VERSION 5.7 ;
  NOWIREEXTENSIONATPIN ON ;
  DIVIDERCHAR "/" ;
  BUSBITCHARS "[]" ;
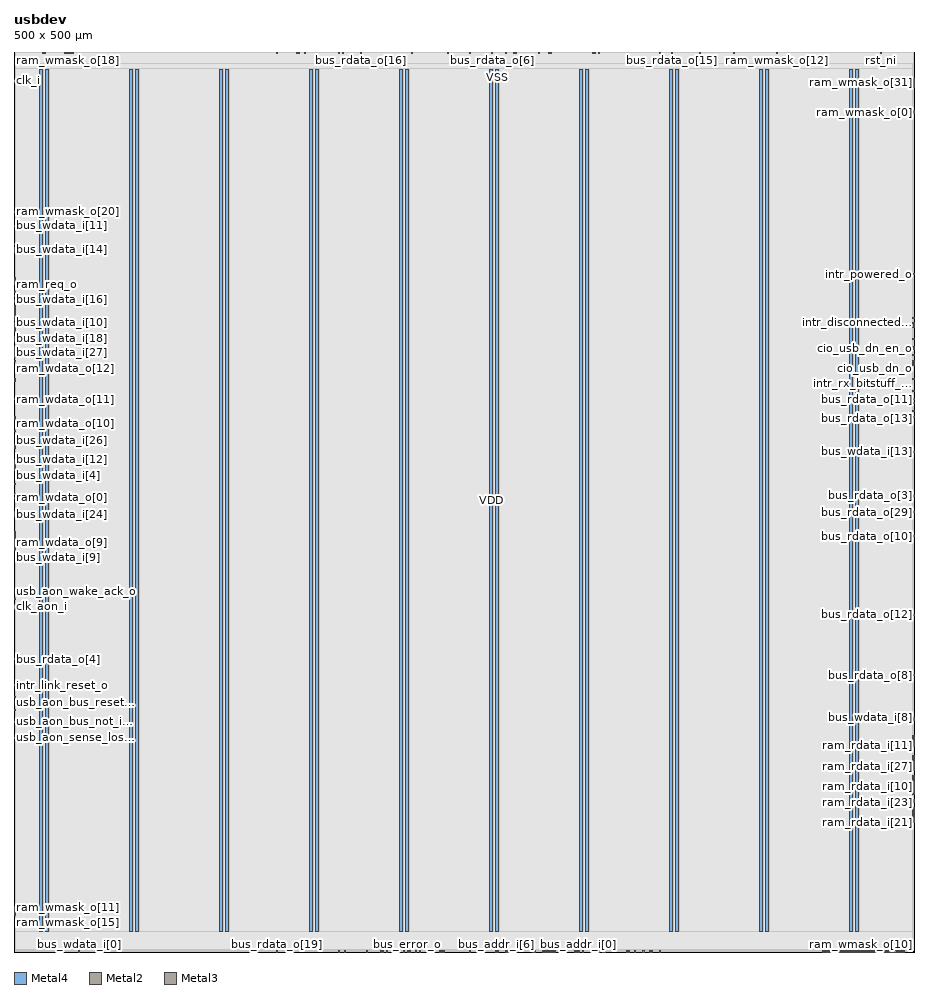
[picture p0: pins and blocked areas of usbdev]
MACRO usbdev
  CLASS BLOCK ;
  FOREIGN usbdev ;
  ORIGIN 0.000 0.000 ;
  SIZE 500.000 BY 500.000 ;
  PIN VDD
    DIRECTION INOUT ;
    USE POWER ;
    PORT
      LAYER Metal4 ;
        RECT 14.280 11.460 15.880 490.300 ;
    END
    PORT
      LAYER Metal4 ;
        RECT 64.280 11.460 65.880 490.300 ;
    END
    PORT
      LAYER Metal4 ;
        RECT 114.280 11.460 115.880 490.300 ;
    END
    PORT
      LAYER Metal4 ;
        RECT 164.280 11.460 165.880 490.300 ;
    END
    PORT
      LAYER Metal4 ;
        RECT 214.280 11.460 215.880 490.300 ;
    END
    PORT
      LAYER Metal4 ;
        RECT 264.280 11.460 265.880 490.300 ;
    END
    PORT
      LAYER Metal4 ;
        RECT 314.280 11.460 315.880 490.300 ;
    END
    PORT
      LAYER Metal4 ;
        RECT 364.280 11.460 365.880 490.300 ;
    END
    PORT
      LAYER Metal4 ;
        RECT 414.280 11.460 415.880 490.300 ;
    END
    PORT
      LAYER Metal4 ;
        RECT 464.280 11.460 465.880 490.300 ;
    END
  END VDD
  PIN VSS
    DIRECTION INOUT ;
    USE GROUND ;
    PORT
      LAYER Metal4 ;
        RECT 17.580 11.460 19.180 490.300 ;
    END
    PORT
      LAYER Metal4 ;
        RECT 67.580 11.460 69.180 490.300 ;
    END
    PORT
      LAYER Metal4 ;
        RECT 117.580 11.460 119.180 490.300 ;
    END
    PORT
      LAYER Metal4 ;
        RECT 167.580 11.460 169.180 490.300 ;
    END
    PORT
      LAYER Metal4 ;
        RECT 217.580 11.460 219.180 490.300 ;
    END
    PORT
      LAYER Metal4 ;
        RECT 267.580 11.460 269.180 490.300 ;
    END
    PORT
      LAYER Metal4 ;
        RECT 317.580 11.460 319.180 490.300 ;
    END
    PORT
      LAYER Metal4 ;
        RECT 367.580 11.460 369.180 490.300 ;
    END
    PORT
      LAYER Metal4 ;
        RECT 417.580 11.460 419.180 490.300 ;
    END
    PORT
      LAYER Metal4 ;
        RECT 467.580 11.460 469.180 490.300 ;
    END
  END VSS
  PIN bus_addr_i[0]
    DIRECTION INPUT ;
    USE SIGNAL ;
    ANTENNAGATEAREA 3.332000 ;
    ANTENNADIFFAREA 1.315500 ;
    PORT
      LAYER Metal2 ;
        RECT 313.600 0.000 314.160 0.560 ;
    END
  END bus_addr_i[0]
  PIN bus_addr_i[10]
    DIRECTION INPUT ;
    USE SIGNAL ;
    ANTENNAGATEAREA 3.998400 ;
    ANTENNADIFFAREA 1.754000 ;
    PORT
      LAYER Metal2 ;
        RECT 295.680 0.000 296.240 0.560 ;
    END
  END bus_addr_i[10]
  PIN bus_addr_i[11]
    DIRECTION INPUT ;
    USE SIGNAL ;
    ANTENNAGATEAREA 3.332000 ;
    ANTENNADIFFAREA 1.315500 ;
    PORT
      LAYER Metal2 ;
        RECT 296.800 0.000 297.360 0.560 ;
    END
  END bus_addr_i[11]
  PIN bus_addr_i[1]
    DIRECTION INPUT ;
    USE SIGNAL ;
    ANTENNAGATEAREA 3.332000 ;
    ANTENNADIFFAREA 1.315500 ;
    PORT
      LAYER Metal2 ;
        RECT 311.360 0.000 311.920 0.560 ;
    END
  END bus_addr_i[1]
  PIN bus_addr_i[2]
    DIRECTION INPUT ;
    USE SIGNAL ;
    ANTENNAGATEAREA 10.662399 ;
    ANTENNADIFFAREA 4.385000 ;
    PORT
      LAYER Metal2 ;
        RECT 287.840 0.000 288.400 0.560 ;
    END
  END bus_addr_i[2]
  PIN bus_addr_i[3]
    DIRECTION INPUT ;
    USE SIGNAL ;
    ANTENNAGATEAREA 6.664000 ;
    ANTENNADIFFAREA 2.631000 ;
    PORT
      LAYER Metal2 ;
        RECT 288.960 0.000 289.520 0.560 ;
    END
  END bus_addr_i[3]
  PIN bus_addr_i[4]
    DIRECTION INPUT ;
    USE SIGNAL ;
    ANTENNAGATEAREA 4.664800 ;
    ANTENNADIFFAREA 2.192500 ;
    PORT
      LAYER Metal2 ;
        RECT 294.560 0.000 295.120 0.560 ;
    END
  END bus_addr_i[4]
  PIN bus_addr_i[5]
    DIRECTION INPUT ;
    USE SIGNAL ;
    ANTENNAGATEAREA 5.997600 ;
    ANTENNADIFFAREA 2.631000 ;
    PORT
      LAYER Metal2 ;
        RECT 293.440 0.000 294.000 0.560 ;
    END
  END bus_addr_i[5]
  PIN bus_addr_i[6]
    DIRECTION INPUT ;
    USE SIGNAL ;
    ANTENNAGATEAREA 3.998400 ;
    ANTENNADIFFAREA 1.754000 ;
    PORT
      LAYER Metal2 ;
        RECT 267.680 0.000 268.240 0.560 ;
    END
  END bus_addr_i[6]
  PIN bus_addr_i[7]
    DIRECTION INPUT ;
    USE SIGNAL ;
    ANTENNAGATEAREA 3.998400 ;
    ANTENNADIFFAREA 1.754000 ;
    PORT
      LAYER Metal2 ;
        RECT 268.800 0.000 269.360 0.560 ;
    END
  END bus_addr_i[7]
  PIN bus_addr_i[8]
    DIRECTION INPUT ;
    USE SIGNAL ;
    ANTENNAGATEAREA 3.998400 ;
    ANTENNADIFFAREA 1.754000 ;
    PORT
      LAYER Metal2 ;
        RECT 297.920 0.000 298.480 0.560 ;
    END
  END bus_addr_i[8]
  PIN bus_addr_i[9]
    DIRECTION INPUT ;
    USE SIGNAL ;
    ANTENNAGATEAREA 3.998400 ;
    ANTENNADIFFAREA 1.754000 ;
    PORT
      LAYER Metal2 ;
        RECT 300.160 0.000 300.720 0.560 ;
    END
  END bus_addr_i[9]
  PIN bus_be_i[0]
    DIRECTION INPUT ;
    USE SIGNAL ;
    ANTENNAGATEAREA 1.332800 ;
    ANTENNADIFFAREA 0.877000 ;
    PORT
      LAYER Metal2 ;
        RECT 238.560 0.000 239.120 0.560 ;
    END
  END bus_be_i[0]
  PIN bus_be_i[1]
    DIRECTION INPUT ;
    USE SIGNAL ;
    ANTENNAGATEAREA 0.666400 ;
    ANTENNADIFFAREA 0.438500 ;
    PORT
      LAYER Metal2 ;
        RECT 236.320 0.000 236.880 0.560 ;
    END
  END bus_be_i[1]
  PIN bus_be_i[2]
    DIRECTION INPUT ;
    USE SIGNAL ;
    ANTENNAGATEAREA 1.332800 ;
    ANTENNADIFFAREA 0.438500 ;
    PORT
      LAYER Metal2 ;
        RECT 237.440 0.000 238.000 0.560 ;
    END
  END bus_be_i[2]
  PIN bus_be_i[3]
    DIRECTION INPUT ;
    USE SIGNAL ;
    ANTENNAGATEAREA 1.332800 ;
    ANTENNADIFFAREA 0.438500 ;
    PORT
      LAYER Metal2 ;
        RECT 230.720 0.000 231.280 0.560 ;
    END
  END bus_be_i[3]
  PIN bus_error_o
    DIRECTION OUTPUT ;
    USE SIGNAL ;
    ANTENNAGATEAREA 0.666400 ;
    ANTENNADIFFAREA 1.237600 ;
    PORT
      LAYER Metal2 ;
        RECT 218.400 0.000 218.960 0.560 ;
    END
  END bus_error_o
  PIN bus_rdata_o[0]
    DIRECTION OUTPUT ;
    USE SIGNAL ;
    ANTENNADIFFAREA 1.237600 ;
    PORT
      LAYER Metal2 ;
        RECT 253.120 0.000 253.680 0.560 ;
    END
  END bus_rdata_o[0]
  PIN bus_rdata_o[10]
    DIRECTION OUTPUT ;
    USE SIGNAL ;
    ANTENNADIFFAREA 1.955200 ;
    PORT
      LAYER Metal3 ;
        RECT 499.440 230.720 500.000 231.280 ;
    END
  END bus_rdata_o[10]
  PIN bus_rdata_o[11]
    DIRECTION OUTPUT ;
    USE SIGNAL ;
    ANTENNADIFFAREA 1.955200 ;
    PORT
      LAYER Metal3 ;
        RECT 499.440 306.880 500.000 307.440 ;
    END
  END bus_rdata_o[11]
  PIN bus_rdata_o[12]
    DIRECTION OUTPUT ;
    USE SIGNAL ;
    ANTENNADIFFAREA 3.390400 ;
    PORT
      LAYER Metal3 ;
        RECT 499.440 187.040 500.000 187.600 ;
    END
  END bus_rdata_o[12]
  PIN bus_rdata_o[13]
    DIRECTION OUTPUT ;
    USE SIGNAL ;
    ANTENNADIFFAREA 1.955200 ;
    PORT
      LAYER Metal3 ;
        RECT 499.440 300.160 500.000 300.720 ;
    END
  END bus_rdata_o[13]
  PIN bus_rdata_o[14]
    DIRECTION OUTPUT ;
    USE SIGNAL ;
    ANTENNADIFFAREA 1.955200 ;
    PORT
      LAYER Metal3 ;
        RECT 499.440 296.800 500.000 297.360 ;
    END
  END bus_rdata_o[14]
  PIN bus_rdata_o[15]
    DIRECTION OUTPUT ;
    USE SIGNAL ;
    ANTENNADIFFAREA 1.237600 ;
    PORT
      LAYER Metal2 ;
        RECT 365.120 499.440 365.680 500.000 ;
    END
  END bus_rdata_o[15]
  PIN bus_rdata_o[16]
    DIRECTION OUTPUT ;
    USE SIGNAL ;
    ANTENNADIFFAREA 1.237600 ;
    PORT
      LAYER Metal2 ;
        RECT 192.640 499.440 193.200 500.000 ;
    END
  END bus_rdata_o[16]
  PIN bus_rdata_o[17]
    DIRECTION OUTPUT ;
    USE SIGNAL ;
    ANTENNADIFFAREA 1.237600 ;
    PORT
      LAYER Metal2 ;
        RECT 156.800 499.440 157.360 500.000 ;
    END
  END bus_rdata_o[17]
  PIN bus_rdata_o[18]
    DIRECTION OUTPUT ;
    USE SIGNAL ;
    ANTENNADIFFAREA 1.237600 ;
    PORT
      LAYER Metal2 ;
        RECT 145.600 499.440 146.160 500.000 ;
    END
  END bus_rdata_o[18]
  PIN bus_rdata_o[19]
    DIRECTION OUTPUT ;
    USE SIGNAL ;
    ANTENNADIFFAREA 1.237600 ;
    PORT
      LAYER Metal2 ;
        RECT 145.600 0.000 146.160 0.560 ;
    END
  END bus_rdata_o[19]
  PIN bus_rdata_o[1]
    DIRECTION OUTPUT ;
    USE SIGNAL ;
    ANTENNADIFFAREA 2.672800 ;
    PORT
      LAYER Metal2 ;
        RECT 260.960 0.000 261.520 0.560 ;
    END
  END bus_rdata_o[1]
  PIN bus_rdata_o[20]
    DIRECTION OUTPUT ;
    USE SIGNAL ;
    ANTENNADIFFAREA 1.237600 ;
    PORT
      LAYER Metal2 ;
        RECT 161.280 499.440 161.840 500.000 ;
    END
  END bus_rdata_o[20]
  PIN bus_rdata_o[21]
    DIRECTION OUTPUT ;
    USE SIGNAL ;
    ANTENNADIFFAREA 1.237600 ;
    PORT
      LAYER Metal2 ;
        RECT 180.320 499.440 180.880 500.000 ;
    END
  END bus_rdata_o[21]
  PIN bus_rdata_o[22]
    DIRECTION OUTPUT ;
    USE SIGNAL ;
    ANTENNADIFFAREA 1.237600 ;
    PORT
      LAYER Metal2 ;
        RECT 183.680 0.000 184.240 0.560 ;
    END
  END bus_rdata_o[22]
  PIN bus_rdata_o[23]
    DIRECTION OUTPUT ;
    USE SIGNAL ;
    ANTENNADIFFAREA 1.237600 ;
    PORT
      LAYER Metal2 ;
        RECT 353.920 0.000 354.480 0.560 ;
    END
  END bus_rdata_o[23]
  PIN bus_rdata_o[24]
    DIRECTION OUTPUT ;
    USE SIGNAL ;
    ANTENNADIFFAREA 1.439900 ;
    PORT
      LAYER Metal2 ;
        RECT 196.000 0.000 196.560 0.560 ;
    END
  END bus_rdata_o[24]
  PIN bus_rdata_o[25]
    DIRECTION OUTPUT ;
    USE SIGNAL ;
    ANTENNADIFFAREA 1.439900 ;
    PORT
      LAYER Metal2 ;
        RECT 203.840 0.000 204.400 0.560 ;
    END
  END bus_rdata_o[25]
  PIN bus_rdata_o[26]
    DIRECTION OUTPUT ;
    USE SIGNAL ;
    ANTENNADIFFAREA 1.439900 ;
    PORT
      LAYER Metal2 ;
        RECT 207.200 0.000 207.760 0.560 ;
    END
  END bus_rdata_o[26]
  PIN bus_rdata_o[27]
    DIRECTION OUTPUT ;
    USE SIGNAL ;
    ANTENNADIFFAREA 1.237600 ;
    PORT
      LAYER Metal2 ;
        RECT 219.520 0.000 220.080 0.560 ;
    END
  END bus_rdata_o[27]
  PIN bus_rdata_o[28]
    DIRECTION OUTPUT ;
    USE SIGNAL ;
    ANTENNADIFFAREA 1.439900 ;
    PORT
      LAYER Metal2 ;
        RECT 220.640 499.440 221.200 500.000 ;
    END
  END bus_rdata_o[28]
  PIN bus_rdata_o[29]
    DIRECTION OUTPUT ;
    USE SIGNAL ;
    ANTENNADIFFAREA 1.237600 ;
    PORT
      LAYER Metal3 ;
        RECT 499.440 244.160 500.000 244.720 ;
    END
  END bus_rdata_o[29]
  PIN bus_rdata_o[2]
    DIRECTION OUTPUT ;
    USE SIGNAL ;
    ANTENNADIFFAREA 1.955200 ;
    PORT
      LAYER Metal3 ;
        RECT 499.440 304.640 500.000 305.200 ;
    END
  END bus_rdata_o[2]
  PIN bus_rdata_o[30]
    DIRECTION OUTPUT ;
    USE SIGNAL ;
    ANTENNADIFFAREA 1.237600 ;
    PORT
      LAYER Metal2 ;
        RECT 349.440 0.000 350.000 0.560 ;
    END
  END bus_rdata_o[30]
  PIN bus_rdata_o[31]
    DIRECTION OUTPUT ;
    USE SIGNAL ;
    ANTENNADIFFAREA 1.237600 ;
    PORT
      LAYER Metal2 ;
        RECT 321.440 0.000 322.000 0.560 ;
    END
  END bus_rdata_o[31]
  PIN bus_rdata_o[3]
    DIRECTION OUTPUT ;
    USE SIGNAL ;
    ANTENNADIFFAREA 1.955200 ;
    PORT
      LAYER Metal3 ;
        RECT 499.440 253.120 500.000 253.680 ;
    END
  END bus_rdata_o[3]
  PIN bus_rdata_o[4]
    DIRECTION OUTPUT ;
    USE SIGNAL ;
    ANTENNADIFFAREA 1.955200 ;
    PORT
      LAYER Metal3 ;
        RECT 0.000 162.400 0.560 162.960 ;
    END
  END bus_rdata_o[4]
  PIN bus_rdata_o[5]
    DIRECTION OUTPUT ;
    USE SIGNAL ;
    ANTENNADIFFAREA 1.955200 ;
    PORT
      LAYER Metal2 ;
        RECT 240.800 499.440 241.360 500.000 ;
    END
  END bus_rdata_o[5]
  PIN bus_rdata_o[6]
    DIRECTION OUTPUT ;
    USE SIGNAL ;
    ANTENNADIFFAREA 1.237600 ;
    PORT
      LAYER Metal2 ;
        RECT 265.440 499.440 266.000 500.000 ;
    END
  END bus_rdata_o[6]
  PIN bus_rdata_o[7]
    DIRECTION OUTPUT ;
    USE SIGNAL ;
    ANTENNADIFFAREA 1.237600 ;
    PORT
      LAYER Metal2 ;
        RECT 182.560 499.440 183.120 500.000 ;
    END
  END bus_rdata_o[7]
  PIN bus_rdata_o[8]
    DIRECTION OUTPUT ;
    USE SIGNAL ;
    ANTENNADIFFAREA 1.955200 ;
    PORT
      LAYER Metal3 ;
        RECT 499.440 153.440 500.000 154.000 ;
    END
  END bus_rdata_o[8]
  PIN bus_rdata_o[9]
    DIRECTION OUTPUT ;
    USE SIGNAL ;
    ANTENNADIFFAREA 1.955200 ;
    PORT
      LAYER Metal2 ;
        RECT 340.480 0.000 341.040 0.560 ;
    END
  END bus_rdata_o[9]
  PIN bus_re_i
    DIRECTION INPUT ;
    USE SIGNAL ;
    ANTENNAGATEAREA 1.999200 ;
    ANTENNADIFFAREA 0.877000 ;
    PORT
      LAYER Metal2 ;
        RECT 216.160 0.000 216.720 0.560 ;
    END
  END bus_re_i
  PIN bus_wdata_i[0]
    DIRECTION INPUT ;
    USE SIGNAL ;
    ANTENNAGATEAREA 10.584000 ;
    ANTENNADIFFAREA 6.139000 ;
    PORT
      LAYER Metal2 ;
        RECT 35.840 0.000 36.400 0.560 ;
    END
  END bus_wdata_i[0]
  PIN bus_wdata_i[10]
    DIRECTION INPUT ;
    USE SIGNAL ;
    ANTENNAGATEAREA 2.430400 ;
    ANTENNADIFFAREA 0.877000 ;
    PORT
      LAYER Metal3 ;
        RECT 0.000 349.440 0.560 350.000 ;
    END
  END bus_wdata_i[10]
  PIN bus_wdata_i[11]
    DIRECTION INPUT ;
    USE SIGNAL ;
    ANTENNAGATEAREA 1.254400 ;
    ANTENNADIFFAREA 0.877000 ;
    PORT
      LAYER Metal3 ;
        RECT 0.000 403.200 0.560 403.760 ;
    END
  END bus_wdata_i[11]
  PIN bus_wdata_i[12]
    DIRECTION INPUT ;
    USE SIGNAL ;
    ANTENNAGATEAREA 1.254400 ;
    ANTENNADIFFAREA 0.877000 ;
    PORT
      LAYER Metal3 ;
        RECT 0.000 273.280 0.560 273.840 ;
    END
  END bus_wdata_i[12]
  PIN bus_wdata_i[13]
    DIRECTION INPUT ;
    USE SIGNAL ;
    ANTENNAGATEAREA 7.918400 ;
    ANTENNADIFFAREA 4.385000 ;
    PORT
      LAYER Metal3 ;
        RECT 499.440 277.760 500.000 278.320 ;
    END
  END bus_wdata_i[13]
  PIN bus_wdata_i[14]
    DIRECTION INPUT ;
    USE SIGNAL ;
    ANTENNAGATEAREA 3.096800 ;
    ANTENNADIFFAREA 1.315500 ;
    PORT
      LAYER Metal3 ;
        RECT 0.000 389.760 0.560 390.320 ;
    END
  END bus_wdata_i[14]
  PIN bus_wdata_i[15]
    DIRECTION INPUT ;
    USE SIGNAL ;
    ANTENNAGATEAREA 1.999200 ;
    ANTENNADIFFAREA 1.315500 ;
    PORT
      LAYER Metal3 ;
        RECT 0.000 388.640 0.560 389.200 ;
    END
  END bus_wdata_i[15]
  PIN bus_wdata_i[16]
    DIRECTION INPUT ;
    USE SIGNAL ;
    ANTENNAGATEAREA 1.332800 ;
    ANTENNADIFFAREA 0.877000 ;
    PORT
      LAYER Metal3 ;
        RECT 0.000 366.240 0.560 366.800 ;
    END
  END bus_wdata_i[16]
  PIN bus_wdata_i[17]
    DIRECTION INPUT ;
    USE SIGNAL ;
    ANTENNAGATEAREA 3.763200 ;
    ANTENNADIFFAREA 1.754000 ;
    PORT
      LAYER Metal3 ;
        RECT 0.000 272.160 0.560 272.720 ;
    END
  END bus_wdata_i[17]
  PIN bus_wdata_i[18]
    DIRECTION INPUT ;
    USE SIGNAL ;
    ANTENNAGATEAREA 6.664000 ;
    ANTENNADIFFAREA 3.946500 ;
    PORT
      LAYER Metal3 ;
        RECT 0.000 344.960 0.560 345.520 ;
    END
  END bus_wdata_i[18]
  PIN bus_wdata_i[19]
    DIRECTION INPUT ;
    USE SIGNAL ;
    ANTENNAGATEAREA 7.330400 ;
    ANTENNADIFFAREA 3.946500 ;
    PORT
      LAYER Metal3 ;
        RECT 0.000 339.360 0.560 339.920 ;
    END
  END bus_wdata_i[19]
  PIN bus_wdata_i[1]
    DIRECTION INPUT ;
    USE SIGNAL ;
    ANTENNAGATEAREA 3.998400 ;
    ANTENNADIFFAREA 1.754000 ;
    PORT
      LAYER Metal3 ;
        RECT 0.000 271.040 0.560 271.600 ;
    END
  END bus_wdata_i[1]
  PIN bus_wdata_i[20]
    DIRECTION INPUT ;
    USE SIGNAL ;
    ANTENNAGATEAREA 5.997600 ;
    ANTENNADIFFAREA 3.508000 ;
    PORT
      LAYER Metal3 ;
        RECT 0.000 340.480 0.560 341.040 ;
    END
  END bus_wdata_i[20]
  PIN bus_wdata_i[21]
    DIRECTION INPUT ;
    USE SIGNAL ;
    ANTENNAGATEAREA 7.330400 ;
    ANTENNADIFFAREA 3.946500 ;
    PORT
      LAYER Metal3 ;
        RECT 0.000 351.680 0.560 352.240 ;
    END
  END bus_wdata_i[21]
  PIN bus_wdata_i[22]
    DIRECTION INPUT ;
    USE SIGNAL ;
    ANTENNAGATEAREA 1.332800 ;
    ANTENNADIFFAREA 0.877000 ;
    PORT
      LAYER Metal3 ;
        RECT 0.000 364.000 0.560 364.560 ;
    END
  END bus_wdata_i[22]
  PIN bus_wdata_i[23]
    DIRECTION INPUT ;
    USE SIGNAL ;
    ANTENNAGATEAREA 0.666400 ;
    ANTENNADIFFAREA 0.438500 ;
    PORT
      LAYER Metal3 ;
        RECT 0.000 357.280 0.560 357.840 ;
    END
  END bus_wdata_i[23]
  PIN bus_wdata_i[24]
    DIRECTION INPUT ;
    USE SIGNAL ;
    ANTENNAGATEAREA 0.666400 ;
    ANTENNADIFFAREA 0.438500 ;
    PORT
      LAYER Metal3 ;
        RECT 0.000 243.040 0.560 243.600 ;
    END
  END bus_wdata_i[24]
  PIN bus_wdata_i[25]
    DIRECTION INPUT ;
    USE SIGNAL ;
    ANTENNAGATEAREA 0.666400 ;
    ANTENNADIFFAREA 0.438500 ;
    PORT
      LAYER Metal3 ;
        RECT 0.000 232.960 0.560 233.520 ;
    END
  END bus_wdata_i[25]
  PIN bus_wdata_i[26]
    DIRECTION INPUT ;
    USE SIGNAL ;
    ANTENNAGATEAREA 0.666400 ;
    ANTENNADIFFAREA 0.438500 ;
    PORT
      LAYER Metal3 ;
        RECT 0.000 280.000 0.560 280.560 ;
    END
  END bus_wdata_i[26]
  PIN bus_wdata_i[27]
    DIRECTION INPUT ;
    USE SIGNAL ;
    ANTENNAGATEAREA 1.332800 ;
    ANTENNADIFFAREA 0.877000 ;
    PORT
      LAYER Metal3 ;
        RECT 0.000 332.640 0.560 333.200 ;
    END
  END bus_wdata_i[27]
  PIN bus_wdata_i[28]
    DIRECTION INPUT ;
    USE SIGNAL ;
    ANTENNAGATEAREA 1.332800 ;
    ANTENNADIFFAREA 0.877000 ;
    PORT
      LAYER Metal3 ;
        RECT 0.000 352.800 0.560 353.360 ;
    END
  END bus_wdata_i[28]
  PIN bus_wdata_i[29]
    DIRECTION INPUT ;
    USE SIGNAL ;
    ANTENNAGATEAREA 2.430400 ;
    ANTENNADIFFAREA 0.877000 ;
    PORT
      LAYER Metal3 ;
        RECT 0.000 333.760 0.560 334.320 ;
    END
  END bus_wdata_i[29]
  PIN bus_wdata_i[2]
    DIRECTION INPUT ;
    USE SIGNAL ;
    ANTENNAGATEAREA 3.018400 ;
    ANTENNADIFFAREA 1.315500 ;
    PORT
      LAYER Metal3 ;
        RECT 0.000 393.120 0.560 393.680 ;
    END
  END bus_wdata_i[2]
  PIN bus_wdata_i[30]
    DIRECTION INPUT ;
    USE SIGNAL ;
    ANTENNAGATEAREA 1.332800 ;
    ANTENNADIFFAREA 0.877000 ;
    PORT
      LAYER Metal3 ;
        RECT 0.000 355.040 0.560 355.600 ;
    END
  END bus_wdata_i[30]
  PIN bus_wdata_i[31]
    DIRECTION INPUT ;
    USE SIGNAL ;
    ANTENNAGATEAREA 5.096000 ;
    ANTENNADIFFAREA 2.192500 ;
    PORT
      LAYER Metal3 ;
        RECT 0.000 346.080 0.560 346.640 ;
    END
  END bus_wdata_i[31]
  PIN bus_wdata_i[3]
    DIRECTION INPUT ;
    USE SIGNAL ;
    ANTENNAGATEAREA 5.684000 ;
    ANTENNADIFFAREA 1.754000 ;
    PORT
      LAYER Metal3 ;
        RECT 0.000 269.920 0.560 270.480 ;
    END
  END bus_wdata_i[3]
  PIN bus_wdata_i[4]
    DIRECTION INPUT ;
    USE SIGNAL ;
    ANTENNAGATEAREA 5.096000 ;
    ANTENNADIFFAREA 1.754000 ;
    PORT
      LAYER Metal3 ;
        RECT 0.000 268.800 0.560 269.360 ;
    END
  END bus_wdata_i[4]
  PIN bus_wdata_i[5]
    DIRECTION INPUT ;
    USE SIGNAL ;
    ANTENNAGATEAREA 1.254400 ;
    ANTENNADIFFAREA 0.877000 ;
    PORT
      LAYER Metal3 ;
        RECT 0.000 390.880 0.560 391.440 ;
    END
  END bus_wdata_i[5]
  PIN bus_wdata_i[6]
    DIRECTION INPUT ;
    USE SIGNAL ;
    ANTENNAGATEAREA 1.764000 ;
    ANTENNADIFFAREA 0.438500 ;
    PORT
      LAYER Metal2 ;
        RECT 273.280 499.440 273.840 500.000 ;
    END
  END bus_wdata_i[6]
  PIN bus_wdata_i[7]
    DIRECTION INPUT ;
    USE SIGNAL ;
    ANTENNAGATEAREA 1.999200 ;
    ANTENNADIFFAREA 1.315500 ;
    PORT
      LAYER Metal3 ;
        RECT 0.000 267.680 0.560 268.240 ;
    END
  END bus_wdata_i[7]
  PIN bus_wdata_i[8]
    DIRECTION INPUT ;
    USE SIGNAL ;
    ANTENNAGATEAREA 5.997600 ;
    ANTENNADIFFAREA 3.946500 ;
    PORT
      LAYER Metal3 ;
        RECT 499.440 129.920 500.000 130.480 ;
    END
  END bus_wdata_i[8]
  PIN bus_wdata_i[9]
    DIRECTION INPUT ;
    USE SIGNAL ;
    ANTENNAGATEAREA 2.430400 ;
    ANTENNADIFFAREA 0.877000 ;
    PORT
      LAYER Metal3 ;
        RECT 0.000 222.880 0.560 223.440 ;
    END
  END bus_wdata_i[9]
  PIN bus_we_i
    DIRECTION INPUT ;
    USE SIGNAL ;
    ANTENNAGATEAREA 3.332000 ;
    ANTENNADIFFAREA 1.754000 ;
    PORT
      LAYER Metal2 ;
        RECT 225.120 0.000 225.680 0.560 ;
    END
  END bus_we_i
  PIN cio_sense_i
    DIRECTION INPUT ;
    USE SIGNAL ;
    ANTENNAGATEAREA 0.673300 ;
    ANTENNADIFFAREA 0.438500 ;
    PORT
      LAYER Metal2 ;
        RECT 380.800 499.440 381.360 500.000 ;
    END
  END cio_sense_i
  PIN cio_usb_dn_en_o
    DIRECTION OUTPUT ;
    USE SIGNAL ;
    ANTENNAGATEAREA 0.666400 ;
    ANTENNADIFFAREA 1.285200 ;
    PORT
      LAYER Metal3 ;
        RECT 499.440 334.880 500.000 335.440 ;
    END
  END cio_usb_dn_en_o
  PIN cio_usb_dn_i
    DIRECTION INPUT ;
    USE SIGNAL ;
    ANTENNAGATEAREA 0.673300 ;
    ANTENNADIFFAREA 0.438500 ;
    PORT
      LAYER Metal2 ;
        RECT 277.760 499.440 278.320 500.000 ;
    END
  END cio_usb_dn_i
  PIN cio_usb_dn_o
    DIRECTION OUTPUT ;
    USE SIGNAL ;
    ANTENNADIFFAREA 1.285200 ;
    PORT
      LAYER Metal3 ;
        RECT 499.440 328.160 500.000 328.720 ;
    END
  END cio_usb_dn_o
  PIN cio_usb_dp_en_o
    DIRECTION OUTPUT ;
    USE SIGNAL ;
    ANTENNADIFFAREA 1.237600 ;
    PORT
      LAYER Metal3 ;
        RECT 499.440 336.000 500.000 336.560 ;
    END
  END cio_usb_dp_en_o
  PIN cio_usb_dp_i
    DIRECTION INPUT ;
    USE SIGNAL ;
    ANTENNAGATEAREA 0.673300 ;
    ANTENNADIFFAREA 0.438500 ;
    PORT
      LAYER Metal2 ;
        RECT 278.880 499.440 279.440 500.000 ;
    END
  END cio_usb_dp_i
  PIN cio_usb_dp_o
    DIRECTION OUTPUT ;
    USE SIGNAL ;
    ANTENNADIFFAREA 1.285200 ;
    PORT
      LAYER Metal3 ;
        RECT 499.440 327.040 500.000 327.600 ;
    END
  END cio_usb_dp_o
  PIN clk_aon_i
    DIRECTION INPUT ;
    USE SIGNAL ;
    ANTENNAGATEAREA 2.352000 ;
    ANTENNADIFFAREA 0.438500 ;
    PORT
      LAYER Metal3 ;
        RECT 0.000 191.520 0.560 192.080 ;
    END
  END clk_aon_i
  PIN clk_i
    DIRECTION INPUT ;
    USE SIGNAL ;
    ANTENNAGATEAREA 2.352000 ;
    ANTENNADIFFAREA 0.438500 ;
    PORT
      LAYER Metal3 ;
        RECT 0.000 483.840 0.560 484.400 ;
    END
  END clk_i
  PIN intr_av_out_empty_o
    DIRECTION OUTPUT ;
    USE SIGNAL ;
    ANTENNADIFFAREA 1.237600 ;
    PORT
      LAYER Metal2 ;
        RECT 157.920 499.440 158.480 500.000 ;
    END
  END intr_av_out_empty_o
  PIN intr_av_overflow_o
    DIRECTION OUTPUT ;
    USE SIGNAL ;
    ANTENNADIFFAREA 1.237600 ;
    PORT
      LAYER Metal2 ;
        RECT 358.400 0.000 358.960 0.560 ;
    END
  END intr_av_overflow_o
  PIN intr_av_setup_empty_o
    DIRECTION OUTPUT ;
    USE SIGNAL ;
    ANTENNADIFFAREA 1.237600 ;
    PORT
      LAYER Metal2 ;
        RECT 180.320 0.000 180.880 0.560 ;
    END
  END intr_av_setup_empty_o
  PIN intr_disconnected_o
    DIRECTION OUTPUT ;
    USE SIGNAL ;
    ANTENNADIFFAREA 1.237600 ;
    PORT
      LAYER Metal3 ;
        RECT 499.440 349.440 500.000 350.000 ;
    END
  END intr_disconnected_o
  PIN intr_frame_o
    DIRECTION OUTPUT ;
    USE SIGNAL ;
    ANTENNADIFFAREA 1.237600 ;
    PORT
      LAYER Metal2 ;
        RECT 358.400 499.440 358.960 500.000 ;
    END
  END intr_frame_o
  PIN intr_host_lost_o
    DIRECTION OUTPUT ;
    USE SIGNAL ;
    ANTENNADIFFAREA 1.237600 ;
    PORT
      LAYER Metal2 ;
        RECT 352.800 0.000 353.360 0.560 ;
    END
  END intr_host_lost_o
  PIN intr_link_in_err_o
    DIRECTION OUTPUT ;
    USE SIGNAL ;
    ANTENNADIFFAREA 1.237600 ;
    PORT
      LAYER Metal3 ;
        RECT 499.440 347.200 500.000 347.760 ;
    END
  END intr_link_in_err_o
  PIN intr_link_out_err_o
    DIRECTION OUTPUT ;
    USE SIGNAL ;
    ANTENNADIFFAREA 1.237600 ;
    PORT
      LAYER Metal3 ;
        RECT 499.440 318.080 500.000 318.640 ;
    END
  END intr_link_out_err_o
  PIN intr_link_reset_o
    DIRECTION OUTPUT ;
    USE SIGNAL ;
    ANTENNADIFFAREA 1.237600 ;
    PORT
      LAYER Metal3 ;
        RECT 0.000 147.840 0.560 148.400 ;
    END
  END intr_link_reset_o
  PIN intr_link_resume_o
    DIRECTION OUTPUT ;
    USE SIGNAL ;
    ANTENNADIFFAREA 1.237600 ;
    PORT
      LAYER Metal2 ;
        RECT 291.200 499.440 291.760 500.000 ;
    END
  END intr_link_resume_o
  PIN intr_link_suspend_o
    DIRECTION OUTPUT ;
    USE SIGNAL ;
    ANTENNADIFFAREA 1.237600 ;
    PORT
      LAYER Metal3 ;
        RECT 499.440 351.680 500.000 352.240 ;
    END
  END intr_link_suspend_o
  PIN intr_pkt_received_o
    DIRECTION OUTPUT ;
    USE SIGNAL ;
    ANTENNADIFFAREA 1.237600 ;
    PORT
      LAYER Metal2 ;
        RECT 222.880 0.000 223.440 0.560 ;
    END
  END intr_pkt_received_o
  PIN intr_pkt_sent_o
    DIRECTION OUTPUT ;
    USE SIGNAL ;
    ANTENNADIFFAREA 1.237600 ;
    PORT
      LAYER Metal2 ;
        RECT 341.600 0.000 342.160 0.560 ;
    END
  END intr_pkt_sent_o
  PIN intr_powered_o
    DIRECTION OUTPUT ;
    USE SIGNAL ;
    ANTENNADIFFAREA 1.237600 ;
    PORT
      LAYER Metal3 ;
        RECT 499.440 376.320 500.000 376.880 ;
    END
  END intr_powered_o
  PIN intr_rx_bitstuff_err_o
    DIRECTION OUTPUT ;
    USE SIGNAL ;
    ANTENNADIFFAREA 1.237600 ;
    PORT
      LAYER Metal3 ;
        RECT 499.440 311.360 500.000 311.920 ;
    END
  END intr_rx_bitstuff_err_o
  PIN intr_rx_crc_err_o
    DIRECTION OUTPUT ;
    USE SIGNAL ;
    ANTENNADIFFAREA 1.237600 ;
    PORT
      LAYER Metal2 ;
        RECT 399.840 499.440 400.400 500.000 ;
    END
  END intr_rx_crc_err_o
  PIN intr_rx_full_o
    DIRECTION OUTPUT ;
    USE SIGNAL ;
    ANTENNADIFFAREA 1.237600 ;
    PORT
      LAYER Metal3 ;
        RECT 499.440 128.800 500.000 129.360 ;
    END
  END intr_rx_full_o
  PIN intr_rx_pid_err_o
    DIRECTION OUTPUT ;
    USE SIGNAL ;
    ANTENNADIFFAREA 1.237600 ;
    PORT
      LAYER Metal3 ;
        RECT 499.440 331.520 500.000 332.080 ;
    END
  END intr_rx_pid_err_o
  PIN ram_addr_o[0]
    DIRECTION OUTPUT ;
    USE SIGNAL ;
    ANTENNADIFFAREA 1.439900 ;
    PORT
      LAYER Metal2 ;
        RECT 315.840 0.000 316.400 0.560 ;
    END
  END ram_addr_o[0]
  PIN ram_addr_o[1]
    DIRECTION OUTPUT ;
    USE SIGNAL ;
    ANTENNADIFFAREA 1.439900 ;
    PORT
      LAYER Metal2 ;
        RECT 323.680 0.000 324.240 0.560 ;
    END
  END ram_addr_o[1]
  PIN ram_addr_o[2]
    DIRECTION OUTPUT ;
    USE SIGNAL ;
    ANTENNADIFFAREA 1.439900 ;
    PORT
      LAYER Metal2 ;
        RECT 327.040 0.000 327.600 0.560 ;
    END
  END ram_addr_o[2]
  PIN ram_addr_o[3]
    DIRECTION OUTPUT ;
    USE SIGNAL ;
    ANTENNADIFFAREA 1.439900 ;
    PORT
      LAYER Metal2 ;
        RECT 328.160 0.000 328.720 0.560 ;
    END
  END ram_addr_o[3]
  PIN ram_addr_o[4]
    DIRECTION OUTPUT ;
    USE SIGNAL ;
    ANTENNADIFFAREA 1.439900 ;
    PORT
      LAYER Metal2 ;
        RECT 273.280 0.000 273.840 0.560 ;
    END
  END ram_addr_o[4]
  PIN ram_addr_o[5]
    DIRECTION OUTPUT ;
    USE SIGNAL ;
    ANTENNADIFFAREA 1.439900 ;
    PORT
      LAYER Metal2 ;
        RECT 274.400 0.000 274.960 0.560 ;
    END
  END ram_addr_o[5]
  PIN ram_addr_o[6]
    DIRECTION OUTPUT ;
    USE SIGNAL ;
    ANTENNADIFFAREA 1.439900 ;
    PORT
      LAYER Metal2 ;
        RECT 302.400 0.000 302.960 0.560 ;
    END
  END ram_addr_o[6]
  PIN ram_addr_o[7]
    DIRECTION OUTPUT ;
    USE SIGNAL ;
    ANTENNADIFFAREA 1.439900 ;
    PORT
      LAYER Metal2 ;
        RECT 312.480 0.000 313.040 0.560 ;
    END
  END ram_addr_o[7]
  PIN ram_addr_o[8]
    DIRECTION OUTPUT ;
    USE SIGNAL ;
    ANTENNADIFFAREA 1.439900 ;
    PORT
      LAYER Metal2 ;
        RECT 299.040 0.000 299.600 0.560 ;
    END
  END ram_addr_o[8]
  PIN ram_rdata_i[0]
    DIRECTION INPUT ;
    USE SIGNAL ;
    ANTENNAGATEAREA 1.332800 ;
    ANTENNADIFFAREA 0.877000 ;
    PORT
      LAYER Metal2 ;
        RECT 493.920 0.000 494.480 0.560 ;
    END
  END ram_rdata_i[0]
  PIN ram_rdata_i[10]
    DIRECTION INPUT ;
    USE SIGNAL ;
    ANTENNAGATEAREA 1.332800 ;
    ANTENNADIFFAREA 0.877000 ;
    PORT
      LAYER Metal3 ;
        RECT 499.440 91.840 500.000 92.400 ;
    END
  END ram_rdata_i[10]
  PIN ram_rdata_i[11]
    DIRECTION INPUT ;
    USE SIGNAL ;
    ANTENNAGATEAREA 1.332800 ;
    ANTENNADIFFAREA 0.877000 ;
    PORT
      LAYER Metal3 ;
        RECT 499.440 114.240 500.000 114.800 ;
    END
  END ram_rdata_i[11]
  PIN ram_rdata_i[12]
    DIRECTION INPUT ;
    USE SIGNAL ;
    ANTENNAGATEAREA 1.332800 ;
    ANTENNADIFFAREA 0.877000 ;
    PORT
      LAYER Metal2 ;
        RECT 462.560 0.000 463.120 0.560 ;
    END
  END ram_rdata_i[12]
  PIN ram_rdata_i[13]
    DIRECTION INPUT ;
    USE SIGNAL ;
    ANTENNAGATEAREA 1.332800 ;
    ANTENNADIFFAREA 0.877000 ;
    PORT
      LAYER Metal2 ;
        RECT 491.680 0.000 492.240 0.560 ;
    END
  END ram_rdata_i[13]
  PIN ram_rdata_i[14]
    DIRECTION INPUT ;
    USE SIGNAL ;
    ANTENNAGATEAREA 1.332800 ;
    ANTENNADIFFAREA 0.877000 ;
    PORT
      LAYER Metal2 ;
        RECT 460.320 0.000 460.880 0.560 ;
    END
  END ram_rdata_i[14]
  PIN ram_rdata_i[15]
    DIRECTION INPUT ;
    USE SIGNAL ;
    ANTENNAGATEAREA 1.332800 ;
    ANTENNADIFFAREA 0.877000 ;
    PORT
      LAYER Metal3 ;
        RECT 499.440 73.920 500.000 74.480 ;
    END
  END ram_rdata_i[15]
  PIN ram_rdata_i[16]
    DIRECTION INPUT ;
    USE SIGNAL ;
    ANTENNAGATEAREA 1.332800 ;
    ANTENNADIFFAREA 0.877000 ;
    PORT
      LAYER Metal2 ;
        RECT 469.280 0.000 469.840 0.560 ;
    END
  END ram_rdata_i[16]
  PIN ram_rdata_i[17]
    DIRECTION INPUT ;
    USE SIGNAL ;
    ANTENNAGATEAREA 1.332800 ;
    ANTENNADIFFAREA 0.877000 ;
    PORT
      LAYER Metal3 ;
        RECT 499.440 100.800 500.000 101.360 ;
    END
  END ram_rdata_i[17]
  PIN ram_rdata_i[18]
    DIRECTION INPUT ;
    USE SIGNAL ;
    ANTENNAGATEAREA 1.332800 ;
    ANTENNADIFFAREA 0.877000 ;
    PORT
      LAYER Metal3 ;
        RECT 499.440 107.520 500.000 108.080 ;
    END
  END ram_rdata_i[18]
  PIN ram_rdata_i[19]
    DIRECTION INPUT ;
    USE SIGNAL ;
    ANTENNAGATEAREA 1.332800 ;
    ANTENNADIFFAREA 0.877000 ;
    PORT
      LAYER Metal3 ;
        RECT 499.440 97.440 500.000 98.000 ;
    END
  END ram_rdata_i[19]
  PIN ram_rdata_i[1]
    DIRECTION INPUT ;
    USE SIGNAL ;
    ANTENNAGATEAREA 1.332800 ;
    ANTENNADIFFAREA 0.877000 ;
    PORT
      LAYER Metal3 ;
        RECT 499.440 90.720 500.000 91.280 ;
    END
  END ram_rdata_i[1]
  PIN ram_rdata_i[20]
    DIRECTION INPUT ;
    USE SIGNAL ;
    ANTENNAGATEAREA 1.332800 ;
    ANTENNADIFFAREA 0.877000 ;
    PORT
      LAYER Metal2 ;
        RECT 489.440 0.000 490.000 0.560 ;
    END
  END ram_rdata_i[20]
  PIN ram_rdata_i[21]
    DIRECTION INPUT ;
    USE SIGNAL ;
    ANTENNAGATEAREA 1.332800 ;
    ANTENNADIFFAREA 0.877000 ;
    PORT
      LAYER Metal3 ;
        RECT 499.440 71.680 500.000 72.240 ;
    END
  END ram_rdata_i[21]
  PIN ram_rdata_i[22]
    DIRECTION INPUT ;
    USE SIGNAL ;
    ANTENNAGATEAREA 1.332800 ;
    ANTENNADIFFAREA 0.877000 ;
    PORT
      LAYER Metal2 ;
        RECT 465.920 0.000 466.480 0.560 ;
    END
  END ram_rdata_i[22]
  PIN ram_rdata_i[23]
    DIRECTION INPUT ;
    USE SIGNAL ;
    ANTENNAGATEAREA 1.332800 ;
    ANTENNADIFFAREA 0.877000 ;
    PORT
      LAYER Metal3 ;
        RECT 499.440 78.400 500.000 78.960 ;
    END
  END ram_rdata_i[23]
  PIN ram_rdata_i[24]
    DIRECTION INPUT ;
    USE SIGNAL ;
    ANTENNAGATEAREA 1.332800 ;
    ANTENNADIFFAREA 0.877000 ;
    PORT
      LAYER Metal2 ;
        RECT 458.080 0.000 458.640 0.560 ;
    END
  END ram_rdata_i[24]
  PIN ram_rdata_i[25]
    DIRECTION INPUT ;
    USE SIGNAL ;
    ANTENNAGATEAREA 1.332800 ;
    ANTENNADIFFAREA 0.877000 ;
    PORT
      LAYER Metal3 ;
        RECT 499.440 105.280 500.000 105.840 ;
    END
  END ram_rdata_i[25]
  PIN ram_rdata_i[26]
    DIRECTION INPUT ;
    USE SIGNAL ;
    ANTENNAGATEAREA 1.332800 ;
    ANTENNADIFFAREA 0.877000 ;
    PORT
      LAYER Metal3 ;
        RECT 499.440 116.480 500.000 117.040 ;
    END
  END ram_rdata_i[26]
  PIN ram_rdata_i[27]
    DIRECTION INPUT ;
    USE SIGNAL ;
    ANTENNAGATEAREA 1.332800 ;
    ANTENNADIFFAREA 0.877000 ;
    PORT
      LAYER Metal3 ;
        RECT 499.440 103.040 500.000 103.600 ;
    END
  END ram_rdata_i[27]
  PIN ram_rdata_i[28]
    DIRECTION INPUT ;
    USE SIGNAL ;
    ANTENNAGATEAREA 1.332800 ;
    ANTENNADIFFAREA 0.877000 ;
    PORT
      LAYER Metal2 ;
        RECT 480.480 0.000 481.040 0.560 ;
    END
  END ram_rdata_i[28]
  PIN ram_rdata_i[29]
    DIRECTION INPUT ;
    USE SIGNAL ;
    ANTENNAGATEAREA 1.332800 ;
    ANTENNADIFFAREA 0.877000 ;
    PORT
      LAYER Metal3 ;
        RECT 499.440 82.880 500.000 83.440 ;
    END
  END ram_rdata_i[29]
  PIN ram_rdata_i[2]
    DIRECTION INPUT ;
    USE SIGNAL ;
    ANTENNAGATEAREA 1.332800 ;
    ANTENNADIFFAREA 0.877000 ;
    PORT
      LAYER Metal3 ;
        RECT 499.440 96.320 500.000 96.880 ;
    END
  END ram_rdata_i[2]
  PIN ram_rdata_i[30]
    DIRECTION INPUT ;
    USE SIGNAL ;
    ANTENNAGATEAREA 1.332800 ;
    ANTENNADIFFAREA 0.877000 ;
    PORT
      LAYER Metal2 ;
        RECT 461.440 0.000 462.000 0.560 ;
    END
  END ram_rdata_i[30]
  PIN ram_rdata_i[31]
    DIRECTION INPUT ;
    USE SIGNAL ;
    ANTENNAGATEAREA 1.332800 ;
    ANTENNADIFFAREA 0.877000 ;
    PORT
      LAYER Metal2 ;
        RECT 456.960 0.000 457.520 0.560 ;
    END
  END ram_rdata_i[31]
  PIN ram_rdata_i[3]
    DIRECTION INPUT ;
    USE SIGNAL ;
    ANTENNAGATEAREA 1.332800 ;
    ANTENNADIFFAREA 0.877000 ;
    PORT
      LAYER Metal3 ;
        RECT 499.440 118.720 500.000 119.280 ;
    END
  END ram_rdata_i[3]
  PIN ram_rdata_i[4]
    DIRECTION INPUT ;
    USE SIGNAL ;
    ANTENNAGATEAREA 1.332800 ;
    ANTENNADIFFAREA 0.877000 ;
    PORT
      LAYER Metal2 ;
        RECT 470.400 0.000 470.960 0.560 ;
    END
  END ram_rdata_i[4]
  PIN ram_rdata_i[5]
    DIRECTION INPUT ;
    USE SIGNAL ;
    ANTENNAGATEAREA 1.332800 ;
    ANTENNADIFFAREA 0.877000 ;
    PORT
      LAYER Metal2 ;
        RECT 481.600 0.000 482.160 0.560 ;
    END
  END ram_rdata_i[5]
  PIN ram_rdata_i[6]
    DIRECTION INPUT ;
    USE SIGNAL ;
    ANTENNAGATEAREA 1.332800 ;
    ANTENNADIFFAREA 0.877000 ;
    PORT
      LAYER Metal2 ;
        RECT 459.200 0.000 459.760 0.560 ;
    END
  END ram_rdata_i[6]
  PIN ram_rdata_i[7]
    DIRECTION INPUT ;
    USE SIGNAL ;
    ANTENNAGATEAREA 1.332800 ;
    ANTENNADIFFAREA 0.877000 ;
    PORT
      LAYER Metal3 ;
        RECT 499.440 76.160 500.000 76.720 ;
    END
  END ram_rdata_i[7]
  PIN ram_rdata_i[8]
    DIRECTION INPUT ;
    USE SIGNAL ;
    ANTENNAGATEAREA 1.332800 ;
    ANTENNADIFFAREA 0.877000 ;
    PORT
      LAYER Metal2 ;
        RECT 450.240 0.000 450.800 0.560 ;
    END
  END ram_rdata_i[8]
  PIN ram_rdata_i[9]
    DIRECTION INPUT ;
    USE SIGNAL ;
    ANTENNAGATEAREA 1.332800 ;
    ANTENNADIFFAREA 0.877000 ;
    PORT
      LAYER Metal3 ;
        RECT 499.440 87.360 500.000 87.920 ;
    END
  END ram_rdata_i[9]
  PIN ram_req_o
    DIRECTION OUTPUT ;
    USE SIGNAL ;
    ANTENNAGATEAREA 15.327200 ;
    ANTENNADIFFAREA 1.237600 ;
    PORT
      LAYER Metal3 ;
        RECT 0.000 370.720 0.560 371.280 ;
    END
  END ram_req_o
  PIN ram_rerror_i[0]
    DIRECTION INPUT ;
    USE SIGNAL ;
    ANTENNAGATEAREA 0.666400 ;
    ANTENNADIFFAREA 0.438500 ;
    PORT
      LAYER Metal3 ;
        RECT 0.000 224.000 0.560 224.560 ;
    END
  END ram_rerror_i[0]
  PIN ram_rerror_i[1]
    DIRECTION INPUT ;
    USE SIGNAL ;
    ANTENNAGATEAREA 0.666400 ;
    ANTENNADIFFAREA 0.438500 ;
    PORT
      LAYER Metal3 ;
        RECT 0.000 226.240 0.560 226.800 ;
    END
  END ram_rerror_i[1]
  PIN ram_rvalid_i
    DIRECTION INPUT ;
    USE SIGNAL ;
    ANTENNAGATEAREA 1.332800 ;
    ANTENNADIFFAREA 0.438500 ;
    PORT
      LAYER Metal3 ;
        RECT 0.000 230.720 0.560 231.280 ;
    END
  END ram_rvalid_i
  PIN ram_wdata_o[0]
    DIRECTION OUTPUT ;
    USE SIGNAL ;
    ANTENNADIFFAREA 1.285200 ;
    PORT
      LAYER Metal3 ;
        RECT 0.000 252.000 0.560 252.560 ;
    END
  END ram_wdata_o[0]
  PIN ram_wdata_o[10]
    DIRECTION OUTPUT ;
    USE SIGNAL ;
    ANTENNADIFFAREA 1.285200 ;
    PORT
      LAYER Metal3 ;
        RECT 0.000 288.960 0.560 289.520 ;
    END
  END ram_wdata_o[10]
  PIN ram_wdata_o[11]
    DIRECTION OUTPUT ;
    USE SIGNAL ;
    ANTENNADIFFAREA 1.285200 ;
    PORT
      LAYER Metal3 ;
        RECT 0.000 306.880 0.560 307.440 ;
    END
  END ram_wdata_o[11]
  PIN ram_wdata_o[12]
    DIRECTION OUTPUT ;
    USE SIGNAL ;
    ANTENNADIFFAREA 1.285200 ;
    PORT
      LAYER Metal3 ;
        RECT 0.000 328.160 0.560 328.720 ;
    END
  END ram_wdata_o[12]
  PIN ram_wdata_o[13]
    DIRECTION OUTPUT ;
    USE SIGNAL ;
    ANTENNADIFFAREA 1.285200 ;
    PORT
      LAYER Metal3 ;
        RECT 0.000 334.880 0.560 335.440 ;
    END
  END ram_wdata_o[13]
  PIN ram_wdata_o[14]
    DIRECTION OUTPUT ;
    USE SIGNAL ;
    ANTENNADIFFAREA 1.285200 ;
    PORT
      LAYER Metal3 ;
        RECT 0.000 371.840 0.560 372.400 ;
    END
  END ram_wdata_o[14]
  PIN ram_wdata_o[15]
    DIRECTION OUTPUT ;
    USE SIGNAL ;
    ANTENNADIFFAREA 1.285200 ;
    PORT
      LAYER Metal3 ;
        RECT 0.000 372.960 0.560 373.520 ;
    END
  END ram_wdata_o[15]
  PIN ram_wdata_o[16]
    DIRECTION OUTPUT ;
    USE SIGNAL ;
    ANTENNADIFFAREA 1.285200 ;
    PORT
      LAYER Metal3 ;
        RECT 0.000 254.240 0.560 254.800 ;
    END
  END ram_wdata_o[16]
  PIN ram_wdata_o[17]
    DIRECTION OUTPUT ;
    USE SIGNAL ;
    ANTENNADIFFAREA 1.285200 ;
    PORT
      LAYER Metal3 ;
        RECT 0.000 259.840 0.560 260.400 ;
    END
  END ram_wdata_o[17]
  PIN ram_wdata_o[18]
    DIRECTION OUTPUT ;
    USE SIGNAL ;
    ANTENNADIFFAREA 1.285200 ;
    PORT
      LAYER Metal3 ;
        RECT 0.000 295.680 0.560 296.240 ;
    END
  END ram_wdata_o[18]
  PIN ram_wdata_o[19]
    DIRECTION OUTPUT ;
    USE SIGNAL ;
    ANTENNADIFFAREA 1.285200 ;
    PORT
      LAYER Metal3 ;
        RECT 0.000 318.080 0.560 318.640 ;
    END
  END ram_wdata_o[19]
  PIN ram_wdata_o[1]
    DIRECTION OUTPUT ;
    USE SIGNAL ;
    ANTENNADIFFAREA 1.285200 ;
    PORT
      LAYER Metal3 ;
        RECT 0.000 241.920 0.560 242.480 ;
    END
  END ram_wdata_o[1]
  PIN ram_wdata_o[20]
    DIRECTION OUTPUT ;
    USE SIGNAL ;
    ANTENNADIFFAREA 1.285200 ;
    PORT
      LAYER Metal3 ;
        RECT 0.000 341.600 0.560 342.160 ;
    END
  END ram_wdata_o[20]
  PIN ram_wdata_o[21]
    DIRECTION OUTPUT ;
    USE SIGNAL ;
    ANTENNADIFFAREA 1.285200 ;
    PORT
      LAYER Metal3 ;
        RECT 0.000 348.320 0.560 348.880 ;
    END
  END ram_wdata_o[21]
  PIN ram_wdata_o[22]
    DIRECTION OUTPUT ;
    USE SIGNAL ;
    ANTENNADIFFAREA 1.285200 ;
    PORT
      LAYER Metal3 ;
        RECT 0.000 361.760 0.560 362.320 ;
    END
  END ram_wdata_o[22]
  PIN ram_wdata_o[23]
    DIRECTION OUTPUT ;
    USE SIGNAL ;
    ANTENNADIFFAREA 1.285200 ;
    PORT
      LAYER Metal3 ;
        RECT 0.000 358.400 0.560 358.960 ;
    END
  END ram_wdata_o[23]
  PIN ram_wdata_o[24]
    DIRECTION OUTPUT ;
    USE SIGNAL ;
    ANTENNADIFFAREA 1.285200 ;
    PORT
      LAYER Metal3 ;
        RECT 0.000 244.160 0.560 244.720 ;
    END
  END ram_wdata_o[24]
  PIN ram_wdata_o[25]
    DIRECTION OUTPUT ;
    USE SIGNAL ;
    ANTENNADIFFAREA 1.285200 ;
    PORT
      LAYER Metal3 ;
        RECT 0.000 229.600 0.560 230.160 ;
    END
  END ram_wdata_o[25]
  PIN ram_wdata_o[26]
    DIRECTION OUTPUT ;
    USE SIGNAL ;
    ANTENNADIFFAREA 1.285200 ;
    PORT
      LAYER Metal3 ;
        RECT 0.000 281.120 0.560 281.680 ;
    END
  END ram_wdata_o[26]
  PIN ram_wdata_o[27]
    DIRECTION OUTPUT ;
    USE SIGNAL ;
    ANTENNADIFFAREA 1.285200 ;
    PORT
      LAYER Metal3 ;
        RECT 0.000 331.520 0.560 332.080 ;
    END
  END ram_wdata_o[27]
  PIN ram_wdata_o[28]
    DIRECTION OUTPUT ;
    USE SIGNAL ;
    ANTENNADIFFAREA 1.285200 ;
    PORT
      LAYER Metal3 ;
        RECT 0.000 350.560 0.560 351.120 ;
    END
  END ram_wdata_o[28]
  PIN ram_wdata_o[29]
    DIRECTION OUTPUT ;
    USE SIGNAL ;
    ANTENNADIFFAREA 1.285200 ;
    PORT
      LAYER Metal3 ;
        RECT 0.000 336.000 0.560 336.560 ;
    END
  END ram_wdata_o[29]
  PIN ram_wdata_o[2]
    DIRECTION OUTPUT ;
    USE SIGNAL ;
    ANTENNADIFFAREA 1.285200 ;
    PORT
      LAYER Metal3 ;
        RECT 0.000 296.800 0.560 297.360 ;
    END
  END ram_wdata_o[2]
  PIN ram_wdata_o[30]
    DIRECTION OUTPUT ;
    USE SIGNAL ;
    ANTENNADIFFAREA 1.285200 ;
    PORT
      LAYER Metal3 ;
        RECT 0.000 356.160 0.560 356.720 ;
    END
  END ram_wdata_o[30]
  PIN ram_wdata_o[31]
    DIRECTION OUTPUT ;
    USE SIGNAL ;
    ANTENNADIFFAREA 1.285200 ;
    PORT
      LAYER Metal3 ;
        RECT 0.000 353.920 0.560 354.480 ;
    END
  END ram_wdata_o[31]
  PIN ram_wdata_o[3]
    DIRECTION OUTPUT ;
    USE SIGNAL ;
    ANTENNADIFFAREA 1.285200 ;
    PORT
      LAYER Metal3 ;
        RECT 0.000 316.960 0.560 317.520 ;
    END
  END ram_wdata_o[3]
  PIN ram_wdata_o[4]
    DIRECTION OUTPUT ;
    USE SIGNAL ;
    ANTENNADIFFAREA 1.285200 ;
    PORT
      LAYER Metal3 ;
        RECT 0.000 330.400 0.560 330.960 ;
    END
  END ram_wdata_o[4]
  PIN ram_wdata_o[5]
    DIRECTION OUTPUT ;
    USE SIGNAL ;
    ANTENNADIFFAREA 1.285200 ;
    PORT
      LAYER Metal3 ;
        RECT 0.000 347.200 0.560 347.760 ;
    END
  END ram_wdata_o[5]
  PIN ram_wdata_o[6]
    DIRECTION OUTPUT ;
    USE SIGNAL ;
    ANTENNADIFFAREA 1.285200 ;
    PORT
      LAYER Metal3 ;
        RECT 0.000 374.080 0.560 374.640 ;
    END
  END ram_wdata_o[6]
  PIN ram_wdata_o[7]
    DIRECTION OUTPUT ;
    USE SIGNAL ;
    ANTENNADIFFAREA 1.285200 ;
    PORT
      LAYER Metal3 ;
        RECT 0.000 360.640 0.560 361.200 ;
    END
  END ram_wdata_o[7]
  PIN ram_wdata_o[8]
    DIRECTION OUTPUT ;
    USE SIGNAL ;
    ANTENNADIFFAREA 1.285200 ;
    PORT
      LAYER Metal2 ;
        RECT 344.960 0.000 345.520 0.560 ;
    END
  END ram_wdata_o[8]
  PIN ram_wdata_o[9]
    DIRECTION OUTPUT ;
    USE SIGNAL ;
    ANTENNADIFFAREA 1.285200 ;
    PORT
      LAYER Metal3 ;
        RECT 0.000 227.360 0.560 227.920 ;
    END
  END ram_wdata_o[9]
  PIN ram_we_o
    DIRECTION OUTPUT ;
    USE SIGNAL ;
    ANTENNADIFFAREA 1.439900 ;
    PORT
      LAYER Metal2 ;
        RECT 324.800 0.000 325.360 0.560 ;
    END
  END ram_we_o
  PIN ram_wmask_o[0]
    DIRECTION OUTPUT ;
    USE SIGNAL ;
    ANTENNADIFFAREA 0.607200 ;
    PORT
      LAYER Metal3 ;
        RECT 499.440 465.920 500.000 466.480 ;
    END
  END ram_wmask_o[0]
  PIN ram_wmask_o[10]
    DIRECTION OUTPUT ;
    USE SIGNAL ;
    ANTENNADIFFAREA 0.607200 ;
    PORT
      LAYER Metal2 ;
        RECT 482.720 0.000 483.280 0.560 ;
    END
  END ram_wmask_o[10]
  PIN ram_wmask_o[11]
    DIRECTION OUTPUT ;
    USE SIGNAL ;
    ANTENNADIFFAREA 0.607200 ;
    PORT
      LAYER Metal3 ;
        RECT 0.000 24.640 0.560 25.200 ;
    END
  END ram_wmask_o[11]
  PIN ram_wmask_o[12]
    DIRECTION OUTPUT ;
    USE SIGNAL ;
    ANTENNADIFFAREA 0.607200 ;
    PORT
      LAYER Metal2 ;
        RECT 423.360 499.440 423.920 500.000 ;
    END
  END ram_wmask_o[12]
  PIN ram_wmask_o[13]
    DIRECTION OUTPUT ;
    USE SIGNAL ;
    ANTENNADIFFAREA 0.607200 ;
    PORT
      LAYER Metal2 ;
        RECT 492.800 0.000 493.360 0.560 ;
    END
  END ram_wmask_o[13]
  PIN ram_wmask_o[14]
    DIRECTION OUTPUT ;
    USE SIGNAL ;
    ANTENNADIFFAREA 0.607200 ;
    PORT
      LAYER Metal2 ;
        RECT 32.480 499.440 33.040 500.000 ;
    END
  END ram_wmask_o[14]
  PIN ram_wmask_o[15]
    DIRECTION OUTPUT ;
    USE SIGNAL ;
    ANTENNADIFFAREA 0.607200 ;
    PORT
      LAYER Metal3 ;
        RECT 0.000 20.160 0.560 20.720 ;
    END
  END ram_wmask_o[15]
  PIN ram_wmask_o[16]
    DIRECTION OUTPUT ;
    USE SIGNAL ;
    ANTENNADIFFAREA 0.607200 ;
    PORT
      LAYER Metal2 ;
        RECT 487.200 0.000 487.760 0.560 ;
    END
  END ram_wmask_o[16]
  PIN ram_wmask_o[17]
    DIRECTION OUTPUT ;
    USE SIGNAL ;
    ANTENNADIFFAREA 0.607200 ;
    PORT
      LAYER Metal3 ;
        RECT 0.000 22.400 0.560 22.960 ;
    END
  END ram_wmask_o[17]
  PIN ram_wmask_o[18]
    DIRECTION OUTPUT ;
    USE SIGNAL ;
    ANTENNADIFFAREA 0.607200 ;
    PORT
      LAYER Metal2 ;
        RECT 15.680 499.440 16.240 500.000 ;
    END
  END ram_wmask_o[18]
  PIN ram_wmask_o[19]
    DIRECTION OUTPUT ;
    USE SIGNAL ;
    ANTENNADIFFAREA 0.607200 ;
    PORT
      LAYER Metal3 ;
        RECT 499.440 480.480 500.000 481.040 ;
    END
  END ram_wmask_o[19]
  PIN ram_wmask_o[1]
    DIRECTION OUTPUT ;
    USE SIGNAL ;
    ANTENNADIFFAREA 0.607200 ;
    PORT
      LAYER Metal2 ;
        RECT 473.760 0.000 474.320 0.560 ;
    END
  END ram_wmask_o[1]
  PIN ram_wmask_o[20]
    DIRECTION OUTPUT ;
    USE SIGNAL ;
    ANTENNADIFFAREA 0.607200 ;
    PORT
      LAYER Metal3 ;
        RECT 0.000 411.040 0.560 411.600 ;
    END
  END ram_wmask_o[20]
  PIN ram_wmask_o[21]
    DIRECTION OUTPUT ;
    USE SIGNAL ;
    ANTENNADIFFAREA 0.607200 ;
    PORT
      LAYER Metal2 ;
        RECT 16.800 499.440 17.360 500.000 ;
    END
  END ram_wmask_o[21]
  PIN ram_wmask_o[22]
    DIRECTION OUTPUT ;
    USE SIGNAL ;
    ANTENNADIFFAREA 0.607200 ;
    PORT
      LAYER Metal2 ;
        RECT 28.000 499.440 28.560 500.000 ;
    END
  END ram_wmask_o[22]
  PIN ram_wmask_o[23]
    DIRECTION OUTPUT ;
    USE SIGNAL ;
    ANTENNADIFFAREA 0.607200 ;
    PORT
      LAYER Metal2 ;
        RECT 488.320 0.000 488.880 0.560 ;
    END
  END ram_wmask_o[23]
  PIN ram_wmask_o[24]
    DIRECTION OUTPUT ;
    USE SIGNAL ;
    ANTENNADIFFAREA 0.607200 ;
    PORT
      LAYER Metal2 ;
        RECT 479.360 0.000 479.920 0.560 ;
    END
  END ram_wmask_o[24]
  PIN ram_wmask_o[25]
    DIRECTION OUTPUT ;
    USE SIGNAL ;
    ANTENNADIFFAREA 0.607200 ;
    PORT
      LAYER Metal2 ;
        RECT 474.880 0.000 475.440 0.560 ;
    END
  END ram_wmask_o[25]
  PIN ram_wmask_o[26]
    DIRECTION OUTPUT ;
    USE SIGNAL ;
    ANTENNADIFFAREA 0.607200 ;
    PORT
      LAYER Metal3 ;
        RECT 499.440 484.960 500.000 485.520 ;
    END
  END ram_wmask_o[26]
  PIN ram_wmask_o[27]
    DIRECTION OUTPUT ;
    USE SIGNAL ;
    ANTENNADIFFAREA 0.607200 ;
    PORT
      LAYER Metal2 ;
        RECT 31.360 499.440 31.920 500.000 ;
    END
  END ram_wmask_o[27]
  PIN ram_wmask_o[28]
    DIRECTION OUTPUT ;
    USE SIGNAL ;
    ANTENNADIFFAREA 0.607200 ;
    PORT
      LAYER Metal2 ;
        RECT 477.120 0.000 477.680 0.560 ;
    END
  END ram_wmask_o[28]
  PIN ram_wmask_o[29]
    DIRECTION OUTPUT ;
    USE SIGNAL ;
    ANTENNADIFFAREA 0.607200 ;
    PORT
      LAYER Metal3 ;
        RECT 499.440 483.840 500.000 484.400 ;
    END
  END ram_wmask_o[29]
  PIN ram_wmask_o[2]
    DIRECTION OUTPUT ;
    USE SIGNAL ;
    ANTENNADIFFAREA 0.607200 ;
    PORT
      LAYER Metal2 ;
        RECT 490.560 0.000 491.120 0.560 ;
    END
  END ram_wmask_o[2]
  PIN ram_wmask_o[30]
    DIRECTION OUTPUT ;
    USE SIGNAL ;
    ANTENNADIFFAREA 0.607200 ;
    PORT
      LAYER Metal3 ;
        RECT 0.000 21.280 0.560 21.840 ;
    END
  END ram_wmask_o[30]
  PIN ram_wmask_o[31]
    DIRECTION OUTPUT ;
    USE SIGNAL ;
    ANTENNADIFFAREA 0.607200 ;
    PORT
      LAYER Metal3 ;
        RECT 499.440 482.720 500.000 483.280 ;
    END
  END ram_wmask_o[31]
  PIN ram_wmask_o[3]
    DIRECTION OUTPUT ;
    USE SIGNAL ;
    ANTENNADIFFAREA 0.607200 ;
    PORT
      LAYER Metal3 ;
        RECT 0.000 23.520 0.560 24.080 ;
    END
  END ram_wmask_o[3]
  PIN ram_wmask_o[4]
    DIRECTION OUTPUT ;
    USE SIGNAL ;
    ANTENNADIFFAREA 0.607200 ;
    PORT
      LAYER Metal2 ;
        RECT 30.240 499.440 30.800 500.000 ;
    END
  END ram_wmask_o[4]
  PIN ram_wmask_o[5]
    DIRECTION OUTPUT ;
    USE SIGNAL ;
    ANTENNADIFFAREA 0.607200 ;
    PORT
      LAYER Metal2 ;
        RECT 472.640 0.000 473.200 0.560 ;
    END
  END ram_wmask_o[5]
  PIN ram_wmask_o[6]
    DIRECTION OUTPUT ;
    USE SIGNAL ;
    ANTENNADIFFAREA 0.607200 ;
    PORT
      LAYER Metal2 ;
        RECT 29.120 499.440 29.680 500.000 ;
    END
  END ram_wmask_o[6]
  PIN ram_wmask_o[7]
    DIRECTION OUTPUT ;
    USE SIGNAL ;
    ANTENNADIFFAREA 0.607200 ;
    PORT
      LAYER Metal3 ;
        RECT 499.440 481.600 500.000 482.160 ;
    END
  END ram_wmask_o[7]
  PIN ram_wmask_o[8]
    DIRECTION OUTPUT ;
    USE SIGNAL ;
    ANTENNADIFFAREA 0.607200 ;
    PORT
      LAYER Metal3 ;
        RECT 499.440 467.040 500.000 467.600 ;
    END
  END ram_wmask_o[8]
  PIN ram_wmask_o[9]
    DIRECTION OUTPUT ;
    USE SIGNAL ;
    ANTENNADIFFAREA 0.607200 ;
    PORT
      LAYER Metal2 ;
        RECT 455.840 0.000 456.400 0.560 ;
    END
  END ram_wmask_o[9]
  PIN rst_aon_ni
    DIRECTION INPUT ;
    USE SIGNAL ;
    ANTENNAGATEAREA 23.990400 ;
    ANTENNADIFFAREA 7.893000 ;
    PORT
      LAYER Metal3 ;
        RECT 0.000 190.400 0.560 190.960 ;
    END
  END rst_aon_ni
  PIN rst_ni
    DIRECTION INPUT ;
    USE SIGNAL ;
    ANTENNAGATEAREA 34.652798 ;
    ANTENNADIFFAREA 10.524000 ;
    PORT
      LAYER Metal2 ;
        RECT 481.600 499.440 482.160 500.000 ;
    END
  END rst_ni
  PIN rx_fifo_rvalid
    DIRECTION OUTPUT ;
    USE SIGNAL ;
    ANTENNAGATEAREA 3.332000 ;
    ANTENNADIFFAREA 1.955200 ;
    PORT
      LAYER Metal2 ;
        RECT 204.960 0.000 205.520 0.560 ;
    END
  END rx_fifo_rvalid
  PIN sw_mem_a_rdata_o[0]
    DIRECTION OUTPUT ;
    USE SIGNAL ;
    ANTENNADIFFAREA 1.237600 ;
    PORT
      LAYER Metal2 ;
        RECT 463.680 0.000 464.240 0.560 ;
    END
  END sw_mem_a_rdata_o[0]
  PIN sw_mem_a_rdata_o[10]
    DIRECTION OUTPUT ;
    USE SIGNAL ;
    ANTENNADIFFAREA 1.237600 ;
    PORT
      LAYER Metal3 ;
        RECT 499.440 92.960 500.000 93.520 ;
    END
  END sw_mem_a_rdata_o[10]
  PIN sw_mem_a_rdata_o[11]
    DIRECTION OUTPUT ;
    USE SIGNAL ;
    ANTENNADIFFAREA 1.237600 ;
    PORT
      LAYER Metal3 ;
        RECT 499.440 115.360 500.000 115.920 ;
    END
  END sw_mem_a_rdata_o[11]
  PIN sw_mem_a_rdata_o[12]
    DIRECTION OUTPUT ;
    USE SIGNAL ;
    ANTENNADIFFAREA 1.237600 ;
    PORT
      LAYER Metal2 ;
        RECT 464.800 0.000 465.360 0.560 ;
    END
  END sw_mem_a_rdata_o[12]
  PIN sw_mem_a_rdata_o[13]
    DIRECTION OUTPUT ;
    USE SIGNAL ;
    ANTENNADIFFAREA 1.237600 ;
    PORT
      LAYER Metal2 ;
        RECT 486.080 0.000 486.640 0.560 ;
    END
  END sw_mem_a_rdata_o[13]
  PIN sw_mem_a_rdata_o[14]
    DIRECTION OUTPUT ;
    USE SIGNAL ;
    ANTENNADIFFAREA 1.237600 ;
    PORT
      LAYER Metal2 ;
        RECT 454.720 0.000 455.280 0.560 ;
    END
  END sw_mem_a_rdata_o[14]
  PIN sw_mem_a_rdata_o[15]
    DIRECTION OUTPUT ;
    USE SIGNAL ;
    ANTENNADIFFAREA 1.237600 ;
    PORT
      LAYER Metal3 ;
        RECT 499.440 75.040 500.000 75.600 ;
    END
  END sw_mem_a_rdata_o[15]
  PIN sw_mem_a_rdata_o[16]
    DIRECTION OUTPUT ;
    USE SIGNAL ;
    ANTENNADIFFAREA 1.237600 ;
    PORT
      LAYER Metal2 ;
        RECT 453.600 0.000 454.160 0.560 ;
    END
  END sw_mem_a_rdata_o[16]
  PIN sw_mem_a_rdata_o[17]
    DIRECTION OUTPUT ;
    USE SIGNAL ;
    ANTENNADIFFAREA 1.237600 ;
    PORT
      LAYER Metal3 ;
        RECT 499.440 101.920 500.000 102.480 ;
    END
  END sw_mem_a_rdata_o[17]
  PIN sw_mem_a_rdata_o[18]
    DIRECTION OUTPUT ;
    USE SIGNAL ;
    ANTENNADIFFAREA 1.237600 ;
    PORT
      LAYER Metal3 ;
        RECT 499.440 108.640 500.000 109.200 ;
    END
  END sw_mem_a_rdata_o[18]
  PIN sw_mem_a_rdata_o[19]
    DIRECTION OUTPUT ;
    USE SIGNAL ;
    ANTENNADIFFAREA 1.237600 ;
    PORT
      LAYER Metal3 ;
        RECT 499.440 95.200 500.000 95.760 ;
    END
  END sw_mem_a_rdata_o[19]
  PIN sw_mem_a_rdata_o[1]
    DIRECTION OUTPUT ;
    USE SIGNAL ;
    ANTENNADIFFAREA 1.237600 ;
    PORT
      LAYER Metal3 ;
        RECT 499.440 89.600 500.000 90.160 ;
    END
  END sw_mem_a_rdata_o[1]
  PIN sw_mem_a_rdata_o[20]
    DIRECTION OUTPUT ;
    USE SIGNAL ;
    ANTENNADIFFAREA 1.237600 ;
    PORT
      LAYER Metal2 ;
        RECT 484.960 0.000 485.520 0.560 ;
    END
  END sw_mem_a_rdata_o[20]
  PIN sw_mem_a_rdata_o[21]
    DIRECTION OUTPUT ;
    USE SIGNAL ;
    ANTENNADIFFAREA 1.237600 ;
    PORT
      LAYER Metal3 ;
        RECT 499.440 72.800 500.000 73.360 ;
    END
  END sw_mem_a_rdata_o[21]
  PIN sw_mem_a_rdata_o[22]
    DIRECTION OUTPUT ;
    USE SIGNAL ;
    ANTENNADIFFAREA 1.237600 ;
    PORT
      LAYER Metal2 ;
        RECT 452.480 0.000 453.040 0.560 ;
    END
  END sw_mem_a_rdata_o[22]
  PIN sw_mem_a_rdata_o[23]
    DIRECTION OUTPUT ;
    USE SIGNAL ;
    ANTENNADIFFAREA 1.237600 ;
    PORT
      LAYER Metal3 ;
        RECT 499.440 79.520 500.000 80.080 ;
    END
  END sw_mem_a_rdata_o[23]
  PIN sw_mem_a_rdata_o[24]
    DIRECTION OUTPUT ;
    USE SIGNAL ;
    ANTENNADIFFAREA 1.237600 ;
    PORT
      LAYER Metal2 ;
        RECT 471.520 0.000 472.080 0.560 ;
    END
  END sw_mem_a_rdata_o[24]
  PIN sw_mem_a_rdata_o[25]
    DIRECTION OUTPUT ;
    USE SIGNAL ;
    ANTENNADIFFAREA 1.237600 ;
    PORT
      LAYER Metal3 ;
        RECT 499.440 106.400 500.000 106.960 ;
    END
  END sw_mem_a_rdata_o[25]
  PIN sw_mem_a_rdata_o[26]
    DIRECTION OUTPUT ;
    USE SIGNAL ;
    ANTENNADIFFAREA 1.237600 ;
    PORT
      LAYER Metal3 ;
        RECT 499.440 117.600 500.000 118.160 ;
    END
  END sw_mem_a_rdata_o[26]
  PIN sw_mem_a_rdata_o[27]
    DIRECTION OUTPUT ;
    USE SIGNAL ;
    ANTENNADIFFAREA 1.237600 ;
    PORT
      LAYER Metal3 ;
        RECT 499.440 104.160 500.000 104.720 ;
    END
  END sw_mem_a_rdata_o[27]
  PIN sw_mem_a_rdata_o[28]
    DIRECTION OUTPUT ;
    USE SIGNAL ;
    ANTENNADIFFAREA 1.237600 ;
    PORT
      LAYER Metal2 ;
        RECT 478.240 0.000 478.800 0.560 ;
    END
  END sw_mem_a_rdata_o[28]
  PIN sw_mem_a_rdata_o[29]
    DIRECTION OUTPUT ;
    USE SIGNAL ;
    ANTENNADIFFAREA 1.237600 ;
    PORT
      LAYER Metal3 ;
        RECT 499.440 84.000 500.000 84.560 ;
    END
  END sw_mem_a_rdata_o[29]
  PIN sw_mem_a_rdata_o[2]
    DIRECTION OUTPUT ;
    USE SIGNAL ;
    ANTENNADIFFAREA 1.237600 ;
    PORT
      LAYER Metal3 ;
        RECT 499.440 94.080 500.000 94.640 ;
    END
  END sw_mem_a_rdata_o[2]
  PIN sw_mem_a_rdata_o[30]
    DIRECTION OUTPUT ;
    USE SIGNAL ;
    ANTENNADIFFAREA 1.237600 ;
    PORT
      LAYER Metal2 ;
        RECT 451.360 0.000 451.920 0.560 ;
    END
  END sw_mem_a_rdata_o[30]
  PIN sw_mem_a_rdata_o[31]
    DIRECTION OUTPUT ;
    USE SIGNAL ;
    ANTENNADIFFAREA 1.237600 ;
    PORT
      LAYER Metal2 ;
        RECT 468.160 0.000 468.720 0.560 ;
    END
  END sw_mem_a_rdata_o[31]
  PIN sw_mem_a_rdata_o[3]
    DIRECTION OUTPUT ;
    USE SIGNAL ;
    ANTENNADIFFAREA 1.237600 ;
    PORT
      LAYER Metal3 ;
        RECT 499.440 119.840 500.000 120.400 ;
    END
  END sw_mem_a_rdata_o[3]
  PIN sw_mem_a_rdata_o[4]
    DIRECTION OUTPUT ;
    USE SIGNAL ;
    ANTENNADIFFAREA 1.237600 ;
    PORT
      LAYER Metal2 ;
        RECT 467.040 0.000 467.600 0.560 ;
    END
  END sw_mem_a_rdata_o[4]
  PIN sw_mem_a_rdata_o[5]
    DIRECTION OUTPUT ;
    USE SIGNAL ;
    ANTENNADIFFAREA 1.237600 ;
    PORT
      LAYER Metal2 ;
        RECT 483.840 0.000 484.400 0.560 ;
    END
  END sw_mem_a_rdata_o[5]
  PIN sw_mem_a_rdata_o[6]
    DIRECTION OUTPUT ;
    USE SIGNAL ;
    ANTENNADIFFAREA 1.237600 ;
    PORT
      LAYER Metal2 ;
        RECT 476.000 0.000 476.560 0.560 ;
    END
  END sw_mem_a_rdata_o[6]
  PIN sw_mem_a_rdata_o[7]
    DIRECTION OUTPUT ;
    USE SIGNAL ;
    ANTENNADIFFAREA 1.237600 ;
    PORT
      LAYER Metal3 ;
        RECT 499.440 77.280 500.000 77.840 ;
    END
  END sw_mem_a_rdata_o[7]
  PIN sw_mem_a_rdata_o[8]
    DIRECTION OUTPUT ;
    USE SIGNAL ;
    ANTENNADIFFAREA 1.237600 ;
    PORT
      LAYER Metal2 ;
        RECT 449.120 0.000 449.680 0.560 ;
    END
  END sw_mem_a_rdata_o[8]
  PIN sw_mem_a_rdata_o[9]
    DIRECTION OUTPUT ;
    USE SIGNAL ;
    ANTENNADIFFAREA 1.237600 ;
    PORT
      LAYER Metal3 ;
        RECT 499.440 88.480 500.000 89.040 ;
    END
  END sw_mem_a_rdata_o[9]
  PIN sw_mem_a_rerror_o[0]
    DIRECTION OUTPUT ;
    USE SIGNAL ;
    ANTENNADIFFAREA 1.237600 ;
    PORT
      LAYER Metal3 ;
        RECT 0.000 228.480 0.560 229.040 ;
    END
  END sw_mem_a_rerror_o[0]
  PIN sw_mem_a_rerror_o[1]
    DIRECTION OUTPUT ;
    USE SIGNAL ;
    ANTENNADIFFAREA 1.237600 ;
    PORT
      LAYER Metal3 ;
        RECT 0.000 231.840 0.560 232.400 ;
    END
  END sw_mem_a_rerror_o[1]
  PIN sw_mem_a_rvalid_o
    DIRECTION OUTPUT ;
    USE SIGNAL ;
    ANTENNAGATEAREA 1.332800 ;
    ANTENNADIFFAREA 2.277600 ;
    PORT
      LAYER Metal3 ;
        RECT 0.000 225.120 0.560 225.680 ;
    END
  END sw_mem_a_rvalid_o
  PIN usb_aon_bus_not_idle_i
    DIRECTION INPUT ;
    USE SIGNAL ;
    ANTENNAGATEAREA 0.673300 ;
    ANTENNADIFFAREA 0.438500 ;
    PORT
      LAYER Metal3 ;
        RECT 0.000 127.680 0.560 128.240 ;
    END
  END usb_aon_bus_not_idle_i
  PIN usb_aon_bus_reset_i
    DIRECTION INPUT ;
    USE SIGNAL ;
    ANTENNAGATEAREA 0.673300 ;
    ANTENNADIFFAREA 0.438500 ;
    PORT
      LAYER Metal3 ;
        RECT 0.000 134.400 0.560 134.960 ;
    END
  END usb_aon_bus_reset_i
  PIN usb_aon_sense_lost_i
    DIRECTION INPUT ;
    USE SIGNAL ;
    ANTENNAGATEAREA 0.673300 ;
    ANTENNADIFFAREA 0.438500 ;
    PORT
      LAYER Metal3 ;
        RECT 0.000 118.720 0.560 119.280 ;
    END
  END usb_aon_sense_lost_i
  PIN usb_aon_suspend_req_o
    DIRECTION OUTPUT ;
    USE SIGNAL ;
    ANTENNADIFFAREA 1.237600 ;
    PORT
      LAYER Metal3 ;
        RECT 0.000 192.640 0.560 193.200 ;
    END
  END usb_aon_suspend_req_o
  PIN usb_aon_wake_ack_o
    DIRECTION OUTPUT ;
    USE SIGNAL ;
    ANTENNADIFFAREA 1.237600 ;
    PORT
      LAYER Metal3 ;
        RECT 0.000 196.000 0.560 196.560 ;
    END
  END usb_aon_wake_ack_o
  PIN usb_aon_wake_detect_active_i
    DIRECTION INPUT ;
    USE SIGNAL ;
    ANTENNAGATEAREA 0.673300 ;
    ANTENNADIFFAREA 0.438500 ;
    PORT
      LAYER Metal3 ;
        RECT 0.000 141.120 0.560 141.680 ;
    END
  END usb_aon_wake_detect_active_i
  PIN usb_dn_pullup_o
    DIRECTION OUTPUT ;
    USE SIGNAL ;
    ANTENNADIFFAREA 1.285200 ;
    PORT
      LAYER Metal2 ;
        RECT 296.800 499.440 297.360 500.000 ;
    END
  END usb_dn_pullup_o
  PIN usb_dp_pullup_o
    DIRECTION OUTPUT ;
    USE SIGNAL ;
    ANTENNADIFFAREA 1.237600 ;
    PORT
      LAYER Metal2 ;
        RECT 297.920 499.440 298.480 500.000 ;
    END
  END usb_dp_pullup_o
  PIN usb_ref_pulse_o
    DIRECTION OUTPUT ;
    USE SIGNAL ;
    ANTENNAGATEAREA 0.666400 ;
    ANTENNADIFFAREA 1.757600 ;
    PORT
      LAYER Metal2 ;
        RECT 321.440 499.440 322.000 500.000 ;
    END
  END usb_ref_pulse_o
  PIN usb_ref_val_o
    DIRECTION OUTPUT ;
    USE SIGNAL ;
    ANTENNAGATEAREA 0.666400 ;
    ANTENNADIFFAREA 1.237600 ;
    PORT
      LAYER Metal2 ;
        RECT 324.800 499.440 325.360 500.000 ;
    END
  END usb_ref_val_o
  PIN usb_rx_d_i
    DIRECTION INPUT ;
    USE SIGNAL ;
    ANTENNAGATEAREA 0.673300 ;
    ANTENNADIFFAREA 0.438500 ;
    PORT
      LAYER Metal2 ;
        RECT 253.120 499.440 253.680 500.000 ;
    END
  END usb_rx_d_i
  PIN usb_rx_enable_o
    DIRECTION OUTPUT ;
    USE SIGNAL ;
    ANTENNADIFFAREA 1.237600 ;
    PORT
      LAYER Metal2 ;
        RECT 322.560 499.440 323.120 500.000 ;
    END
  END usb_rx_enable_o
  PIN usb_tx_d_o
    DIRECTION OUTPUT ;
    USE SIGNAL ;
    ANTENNADIFFAREA 1.285200 ;
    PORT
      LAYER Metal3 ;
        RECT 499.440 340.480 500.000 341.040 ;
    END
  END usb_tx_d_o
  PIN usb_tx_se0_o
    DIRECTION OUTPUT ;
    USE SIGNAL ;
    ANTENNADIFFAREA 1.285200 ;
    PORT
      LAYER Metal3 ;
        RECT 499.440 325.920 500.000 326.480 ;
    END
  END usb_tx_se0_o
  PIN usb_tx_use_d_se0_o
    DIRECTION OUTPUT ;
    USE SIGNAL ;
    ANTENNAGATEAREA 1.332800 ;
    ANTENNADIFFAREA 1.237600 ;
    PORT
      LAYER Metal3 ;
        RECT 499.440 348.320 500.000 348.880 ;
    END
  END usb_tx_use_d_se0_o
  OBS
      LAYER Nwell ;
        RECT 9.650 11.330 490.430 490.430 ;
      LAYER Metal1 ;
        RECT 10.080 11.460 490.000 490.300 ;
      LAYER Metal2 ;
        RECT 0.700 499.140 15.380 499.940 ;
        RECT 17.660 499.140 27.700 499.940 ;
        RECT 33.340 499.140 145.300 499.940 ;
        RECT 146.460 499.140 156.500 499.940 ;
        RECT 158.780 499.140 160.980 499.940 ;
        RECT 162.140 499.140 180.020 499.940 ;
        RECT 181.180 499.140 182.260 499.940 ;
        RECT 183.420 499.140 192.340 499.940 ;
        RECT 193.500 499.140 220.340 499.940 ;
        RECT 221.500 499.140 240.500 499.940 ;
        RECT 241.660 499.140 252.820 499.940 ;
        RECT 253.980 499.140 265.140 499.940 ;
        RECT 266.300 499.140 272.980 499.940 ;
        RECT 274.140 499.140 277.460 499.940 ;
        RECT 279.740 499.140 290.900 499.940 ;
        RECT 292.060 499.140 296.500 499.940 ;
        RECT 298.780 499.140 321.140 499.940 ;
        RECT 323.420 499.140 324.500 499.940 ;
        RECT 325.660 499.140 358.100 499.940 ;
        RECT 359.260 499.140 364.820 499.940 ;
        RECT 365.980 499.140 380.500 499.940 ;
        RECT 381.660 499.140 399.540 499.940 ;
        RECT 400.700 499.140 423.060 499.940 ;
        RECT 424.220 499.140 481.300 499.940 ;
        RECT 482.460 499.140 499.380 499.940 ;
        RECT 0.700 0.860 499.380 499.140 ;
        RECT 0.700 0.140 35.540 0.860 ;
        RECT 36.700 0.140 145.300 0.860 ;
        RECT 146.460 0.140 180.020 0.860 ;
        RECT 181.180 0.140 183.380 0.860 ;
        RECT 184.540 0.140 195.700 0.860 ;
        RECT 196.860 0.140 203.540 0.860 ;
        RECT 205.820 0.140 206.900 0.860 ;
        RECT 208.060 0.140 215.860 0.860 ;
        RECT 217.020 0.140 218.100 0.860 ;
        RECT 220.380 0.140 222.580 0.860 ;
        RECT 223.740 0.140 224.820 0.860 ;
        RECT 225.980 0.140 230.420 0.860 ;
        RECT 231.580 0.140 236.020 0.860 ;
        RECT 239.420 0.140 252.820 0.860 ;
        RECT 253.980 0.140 260.660 0.860 ;
        RECT 261.820 0.140 267.380 0.860 ;
        RECT 269.660 0.140 272.980 0.860 ;
        RECT 275.260 0.140 287.540 0.860 ;
        RECT 289.820 0.140 293.140 0.860 ;
        RECT 301.020 0.140 302.100 0.860 ;
        RECT 303.260 0.140 311.060 0.860 ;
        RECT 314.460 0.140 315.540 0.860 ;
        RECT 316.700 0.140 321.140 0.860 ;
        RECT 322.300 0.140 323.380 0.860 ;
        RECT 325.660 0.140 326.740 0.860 ;
        RECT 329.020 0.140 340.180 0.860 ;
        RECT 342.460 0.140 344.660 0.860 ;
        RECT 345.820 0.140 349.140 0.860 ;
        RECT 350.300 0.140 352.500 0.860 ;
        RECT 354.780 0.140 358.100 0.860 ;
        RECT 359.260 0.140 448.820 0.860 ;
        RECT 494.780 0.140 499.380 0.860 ;
      LAYER Metal3 ;
        RECT 0.560 485.820 499.940 499.940 ;
        RECT 0.560 484.700 499.140 485.820 ;
        RECT 0.860 483.540 499.140 484.700 ;
        RECT 0.560 480.180 499.140 483.540 ;
        RECT 0.560 467.900 499.940 480.180 ;
        RECT 0.560 465.620 499.140 467.900 ;
        RECT 0.560 411.900 499.940 465.620 ;
        RECT 0.860 410.740 499.940 411.900 ;
        RECT 0.560 404.060 499.940 410.740 ;
        RECT 0.860 402.900 499.940 404.060 ;
        RECT 0.560 393.980 499.940 402.900 ;
        RECT 0.860 392.820 499.940 393.980 ;
        RECT 0.560 391.740 499.940 392.820 ;
        RECT 0.860 388.340 499.940 391.740 ;
        RECT 0.560 377.180 499.940 388.340 ;
        RECT 0.560 376.020 499.140 377.180 ;
        RECT 0.560 374.940 499.940 376.020 ;
        RECT 0.860 370.420 499.940 374.940 ;
        RECT 0.560 367.100 499.940 370.420 ;
        RECT 0.860 365.940 499.940 367.100 ;
        RECT 0.560 364.860 499.940 365.940 ;
        RECT 0.860 363.700 499.940 364.860 ;
        RECT 0.560 362.620 499.940 363.700 ;
        RECT 0.860 360.340 499.940 362.620 ;
        RECT 0.560 359.260 499.940 360.340 ;
        RECT 0.860 352.540 499.940 359.260 ;
        RECT 0.860 351.380 499.140 352.540 ;
        RECT 0.860 350.300 499.940 351.380 ;
        RECT 0.860 346.900 499.140 350.300 ;
        RECT 0.860 344.660 499.940 346.900 ;
        RECT 0.560 342.460 499.940 344.660 ;
        RECT 0.860 341.340 499.940 342.460 ;
        RECT 0.860 340.180 499.140 341.340 ;
        RECT 0.860 339.060 499.940 340.180 ;
        RECT 0.560 336.860 499.940 339.060 ;
        RECT 0.860 334.580 499.140 336.860 ;
        RECT 0.860 332.380 499.940 334.580 ;
        RECT 0.860 331.220 499.140 332.380 ;
        RECT 0.860 330.100 499.940 331.220 ;
        RECT 0.560 329.020 499.940 330.100 ;
        RECT 0.860 327.860 499.140 329.020 ;
        RECT 0.560 325.620 499.140 327.860 ;
        RECT 0.560 318.940 499.940 325.620 ;
        RECT 0.860 317.780 499.140 318.940 ;
        RECT 0.860 316.660 499.940 317.780 ;
        RECT 0.560 312.220 499.940 316.660 ;
        RECT 0.560 311.060 499.140 312.220 ;
        RECT 0.560 307.740 499.940 311.060 ;
        RECT 0.860 306.580 499.140 307.740 ;
        RECT 0.560 305.500 499.940 306.580 ;
        RECT 0.560 304.340 499.140 305.500 ;
        RECT 0.560 301.020 499.940 304.340 ;
        RECT 0.560 299.860 499.140 301.020 ;
        RECT 0.560 297.660 499.940 299.860 ;
        RECT 0.860 296.500 499.140 297.660 ;
        RECT 0.860 295.380 499.940 296.500 ;
        RECT 0.560 289.820 499.940 295.380 ;
        RECT 0.860 288.660 499.940 289.820 ;
        RECT 0.560 281.980 499.940 288.660 ;
        RECT 0.860 279.700 499.940 281.980 ;
        RECT 0.560 278.620 499.940 279.700 ;
        RECT 0.560 277.460 499.140 278.620 ;
        RECT 0.560 274.140 499.940 277.460 ;
        RECT 0.860 267.380 499.940 274.140 ;
        RECT 0.560 260.700 499.940 267.380 ;
        RECT 0.860 259.540 499.940 260.700 ;
        RECT 0.560 255.100 499.940 259.540 ;
        RECT 0.860 253.980 499.940 255.100 ;
        RECT 0.860 253.940 499.140 253.980 ;
        RECT 0.560 252.860 499.140 253.940 ;
        RECT 0.860 252.820 499.140 252.860 ;
        RECT 0.860 251.700 499.940 252.820 ;
        RECT 0.560 245.020 499.940 251.700 ;
        RECT 0.860 243.860 499.140 245.020 ;
        RECT 0.860 241.620 499.940 243.860 ;
        RECT 0.560 233.820 499.940 241.620 ;
        RECT 0.860 231.580 499.940 233.820 ;
        RECT 0.860 230.420 499.140 231.580 ;
        RECT 0.860 222.580 499.940 230.420 ;
        RECT 0.560 196.860 499.940 222.580 ;
        RECT 0.860 195.700 499.940 196.860 ;
        RECT 0.560 193.500 499.940 195.700 ;
        RECT 0.860 190.100 499.940 193.500 ;
        RECT 0.560 187.900 499.940 190.100 ;
        RECT 0.560 186.740 499.140 187.900 ;
        RECT 0.560 163.260 499.940 186.740 ;
        RECT 0.860 162.100 499.940 163.260 ;
        RECT 0.560 154.300 499.940 162.100 ;
        RECT 0.560 153.140 499.140 154.300 ;
        RECT 0.560 148.700 499.940 153.140 ;
        RECT 0.860 147.540 499.940 148.700 ;
        RECT 0.560 141.980 499.940 147.540 ;
        RECT 0.860 140.820 499.940 141.980 ;
        RECT 0.560 135.260 499.940 140.820 ;
        RECT 0.860 134.100 499.940 135.260 ;
        RECT 0.560 130.780 499.940 134.100 ;
        RECT 0.560 128.540 499.140 130.780 ;
        RECT 0.860 128.500 499.140 128.540 ;
        RECT 0.860 127.380 499.940 128.500 ;
        RECT 0.560 120.700 499.940 127.380 ;
        RECT 0.560 119.580 499.140 120.700 ;
        RECT 0.860 118.420 499.140 119.580 ;
        RECT 0.560 113.940 499.140 118.420 ;
        RECT 0.560 109.500 499.940 113.940 ;
        RECT 0.560 100.500 499.140 109.500 ;
        RECT 0.560 98.300 499.940 100.500 ;
        RECT 0.560 87.060 499.140 98.300 ;
        RECT 0.560 84.860 499.940 87.060 ;
        RECT 0.560 82.580 499.140 84.860 ;
        RECT 0.560 80.380 499.940 82.580 ;
        RECT 0.560 71.380 499.140 80.380 ;
        RECT 0.560 25.500 499.940 71.380 ;
        RECT 0.860 19.860 499.940 25.500 ;
        RECT 0.560 0.700 499.940 19.860 ;
      LAYER Metal4 ;
        RECT 0.700 490.600 499.380 493.830 ;
        RECT 0.700 11.160 13.980 490.600 ;
        RECT 16.180 11.160 17.280 490.600 ;
        RECT 19.480 11.160 63.980 490.600 ;
        RECT 66.180 11.160 67.280 490.600 ;
        RECT 69.480 11.160 113.980 490.600 ;
        RECT 116.180 11.160 117.280 490.600 ;
        RECT 119.480 11.160 163.980 490.600 ;
        RECT 166.180 11.160 167.280 490.600 ;
        RECT 169.480 11.160 213.980 490.600 ;
        RECT 216.180 11.160 217.280 490.600 ;
        RECT 219.480 11.160 263.980 490.600 ;
        RECT 266.180 11.160 267.280 490.600 ;
        RECT 269.480 11.160 313.980 490.600 ;
        RECT 316.180 11.160 317.280 490.600 ;
        RECT 319.480 11.160 363.980 490.600 ;
        RECT 366.180 11.160 367.280 490.600 ;
        RECT 369.480 11.160 413.980 490.600 ;
        RECT 416.180 11.160 417.280 490.600 ;
        RECT 419.480 11.160 463.980 490.600 ;
        RECT 466.180 11.160 467.280 490.600 ;
        RECT 469.480 11.160 499.380 490.600 ;
        RECT 0.700 1.210 499.380 11.160 ;
  END
END usbdev
END LIBRARY

